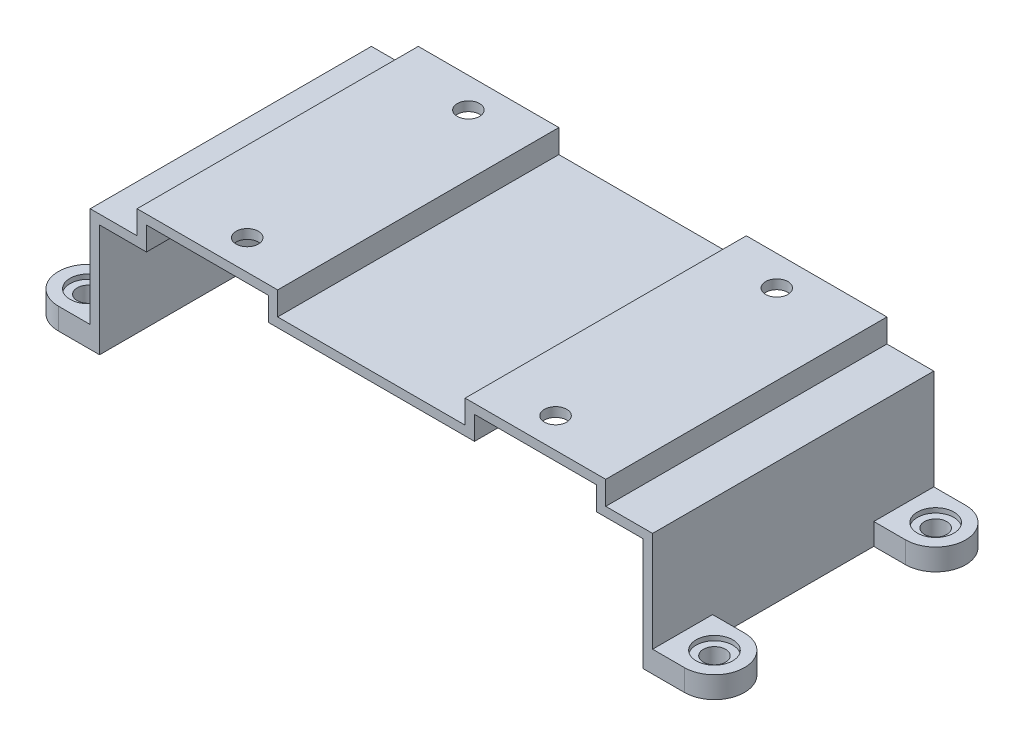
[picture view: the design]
ISO-10303-21;
HEADER;
FILE_DESCRIPTION(('STEP AP214'),'2;1');
FILE_NAME('part.step','',(''),(''),'','','');
FILE_SCHEMA(('AUTOMOTIVE_DESIGN { 1 0 10303 214 1 1 1 1 }'));
ENDSEC;
DATA;
#1=APPLICATION_CONTEXT('core data for automotive mechanical design processes');
#2=APPLICATION_PROTOCOL_DEFINITION('international standard','automotive_design',2000,#1);
#3=PRODUCT_CONTEXT('',#1,'mechanical');
#4=PRODUCT('Part','Part','',(#3));
#5=PRODUCT_RELATED_PRODUCT_CATEGORY('part','',(#4));
#6=PRODUCT_DEFINITION_FORMATION('','',#4);
#7=PRODUCT_DEFINITION_CONTEXT('part definition',#1,'design');
#8=PRODUCT_DEFINITION('design','',#6,#7);
#9=PRODUCT_DEFINITION_SHAPE('','',#8);
#10=(LENGTH_UNIT() NAMED_UNIT(*) SI_UNIT(.MILLI.,.METRE.));
#11=(NAMED_UNIT(*) PLANE_ANGLE_UNIT() SI_UNIT($,.RADIAN.));
#12=(NAMED_UNIT(*) SI_UNIT($,.STERADIAN.) SOLID_ANGLE_UNIT());
#13=UNCERTAINTY_MEASURE_WITH_UNIT(LENGTH_MEASURE(1.E-05),#10,'distance_accuracy_value','');
#14=(GEOMETRIC_REPRESENTATION_CONTEXT(3) GLOBAL_UNCERTAINTY_ASSIGNED_CONTEXT((#13)) GLOBAL_UNIT_ASSIGNED_CONTEXT((#10,
#11,#12)) REPRESENTATION_CONTEXT('',''));
#15=CARTESIAN_POINT('',(0.,0.,0.));
#16=DIRECTION('',(0.,0.,1.));
#17=DIRECTION('',(1.,0.,0.));
#18=AXIS2_PLACEMENT_3D('',#15,#16,#17);
#19=CARTESIAN_POINT('',(-84.836,5.84200000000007,8.12800000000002));
#20=DIRECTION('',(0.,1.,0.));
#21=DIRECTION('',(-1.,0.,0.));
#22=AXIS2_PLACEMENT_3D('',#19,#20,#21);
#23=PLANE('',#22);
#24=DIRECTION('',(0.,0.,-1.));
#25=VECTOR('',#24,1.);
#26=CARTESIAN_POINT('',(-76.2,5.84200000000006,0.));
#27=LINE('',#26,#25);
#28=CARTESIAN_POINT('',(-76.2,5.84200000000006,16.256));
#29=VERTEX_POINT('',#28);
#30=CARTESIAN_POINT('',(-76.2,5.84200000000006,0.));
#31=VERTEX_POINT('',#30);
#32=EDGE_CURVE('E316',#29,#31,#27,.T.);
#33=ORIENTED_EDGE('',*,*,#32,.T.);
#34=DIRECTION('',(-1.,0.,0.));
#35=VECTOR('',#34,1.);
#36=CARTESIAN_POINT('',(-76.2,5.84200000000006,0.));
#37=LINE('',#36,#35);
#38=CARTESIAN_POINT('',(-84.836,5.84200000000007,0.));
#39=VERTEX_POINT('',#38);
#40=EDGE_CURVE('E325',#31,#39,#37,.T.);
#41=ORIENTED_EDGE('',*,*,#40,.T.);
#42=CARTESIAN_POINT('',(-84.836,5.84200000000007,8.12800000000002));
#43=DIRECTION('',(0.,1.,0.));
#44=DIRECTION('',(-1.,0.,0.));
#45=AXIS2_PLACEMENT_3D('',#42,#43,#44);
#46=CIRCLE('',#45,8.128);
#47=CARTESIAN_POINT('',(-84.836,5.84200000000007,16.256));
#48=VERTEX_POINT('',#47);
#49=EDGE_CURVE('E323',#39,#48,#46,.T.);
#50=ORIENTED_EDGE('',*,*,#49,.T.);
#51=DIRECTION('',(1.,0.,0.));
#52=VECTOR('',#51,1.);
#53=CARTESIAN_POINT('',(-76.2,5.84200000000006,16.256));
#54=LINE('',#53,#52);
#55=EDGE_CURVE('E319',#48,#29,#54,.T.);
#56=ORIENTED_EDGE('',*,*,#55,.T.);
#57=EDGE_LOOP('',(#33,#41,#50,#56));
#58=FACE_BOUND('',#57,.T.);
#59=CARTESIAN_POINT('',(-84.836,5.84200000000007,8.12800000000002));
#60=DIRECTION('',(0.,-1.,0.));
#61=DIRECTION('',(-1.,0.,0.));
#62=AXIS2_PLACEMENT_3D('',#59,#60,#61);
#63=CIRCLE('',#62,4.95300000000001);
#64=CARTESIAN_POINT('',(-89.789,5.84200000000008,8.12800000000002));
#65=VERTEX_POINT('',#64);
#66=EDGE_CURVE('E313',#65,#65,#63,.T.);
#67=ORIENTED_EDGE('',*,*,#66,.T.);
#68=EDGE_LOOP('',(#67));
#69=FACE_BOUND('',#68,.T.);
#70=ADVANCED_FACE('F30',(#58,#69),#23,.T.);
#71=CARTESIAN_POINT('',(-76.2,33.02,76.2));
#72=DIRECTION('',(1.,0.,0.));
#73=DIRECTION('',(0.,1.,0.));
#74=AXIS2_PLACEMENT_3D('',#71,#72,#73);
#75=PLANE('',#74);
#76=DIRECTION('',(0.,-1.,0.));
#77=VECTOR('',#76,1.);
#78=CARTESIAN_POINT('',(-76.2,5.84200000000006,16.256));
#79=LINE('',#78,#77);
#80=CARTESIAN_POINT('',(-76.2,0.,16.256));
#81=VERTEX_POINT('',#80);
#82=EDGE_CURVE('E327',#29,#81,#79,.T.);
#83=ORIENTED_EDGE('',*,*,#82,.T.);
#84=DIRECTION('',(0.,0.,-1.));
#85=VECTOR('',#84,1.);
#86=CARTESIAN_POINT('',(-76.2,0.,76.2));
#87=LINE('',#86,#85);
#88=CARTESIAN_POINT('',(-76.2,0.,59.944));
#89=VERTEX_POINT('',#88);
#90=EDGE_CURVE('E707',#89,#81,#87,.T.);
#91=ORIENTED_EDGE('',*,*,#90,.F.);
#92=DIRECTION('',(0.,-1.,0.));
#93=VECTOR('',#92,1.);
#94=CARTESIAN_POINT('',(-76.2,5.84200000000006,59.944));
#95=LINE('',#94,#93);
#96=CARTESIAN_POINT('',(-76.2,5.84200000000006,59.944));
#97=VERTEX_POINT('',#96);
#98=EDGE_CURVE('E771',#97,#89,#95,.T.);
#99=ORIENTED_EDGE('',*,*,#98,.F.);
#100=DIRECTION('',(0.,0.,1.));
#101=VECTOR('',#100,1.);
#102=CARTESIAN_POINT('',(-76.2,5.84200000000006,76.2));
#103=LINE('',#102,#101);
#104=CARTESIAN_POINT('',(-76.2,5.84200000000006,76.2));
#105=VERTEX_POINT('',#104);
#106=EDGE_CURVE('E721',#97,#105,#103,.T.);
#107=ORIENTED_EDGE('',*,*,#106,.T.);
#108=DIRECTION('',(0.,-1.,0.));
#109=VECTOR('',#108,1.);
#110=CARTESIAN_POINT('',(-76.2,33.02,76.2));
#111=LINE('',#110,#109);
#112=CARTESIAN_POINT('',(-76.2,33.02,76.2));
#113=VERTEX_POINT('',#112);
#114=EDGE_CURVE('E715',#113,#105,#111,.T.);
#115=ORIENTED_EDGE('',*,*,#114,.F.);
#116=DIRECTION('',(0.,0.,-1.));
#117=VECTOR('',#116,1.);
#118=CARTESIAN_POINT('',(-76.2,33.02,76.2));
#119=LINE('',#118,#117);
#120=CARTESIAN_POINT('',(-76.2,33.02,0.));
#121=VERTEX_POINT('',#120);
#122=EDGE_CURVE('E710',#113,#121,#119,.T.);
#123=ORIENTED_EDGE('',*,*,#122,.T.);
#124=DIRECTION('',(0.,-1.,0.));
#125=VECTOR('',#124,1.);
#126=CARTESIAN_POINT('',(-76.2,33.02,0.));
#127=LINE('',#126,#125);
#128=EDGE_CURVE('E630',#121,#31,#127,.T.);
#129=ORIENTED_EDGE('',*,*,#128,.T.);
#130=ORIENTED_EDGE('',*,*,#32,.F.);
#131=EDGE_LOOP('',(#83,#91,#99,#107,#115,#123,#129,#130));
#132=FACE_BOUND('',#131,.T.);
#133=ADVANCED_FACE('F439',(#132),#75,.F.);
#134=CARTESIAN_POINT('',(84.836,5.84200000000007,68.072));
#135=DIRECTION('',(0.,1.,0.));
#136=DIRECTION('',(1.,0.,0.));
#137=AXIS2_PLACEMENT_3D('',#134,#135,#136);
#138=PLANE('',#137);
#139=DIRECTION('',(0.,0.,1.));
#140=VECTOR('',#139,1.);
#141=CARTESIAN_POINT('',(76.2,5.84200000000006,76.2));
#142=LINE('',#141,#140);
#143=CARTESIAN_POINT('',(76.2,5.84200000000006,59.944));
#144=VERTEX_POINT('',#143);
#145=CARTESIAN_POINT('',(76.2,5.84200000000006,76.2));
#146=VERTEX_POINT('',#145);
#147=EDGE_CURVE('E352',#144,#146,#142,.T.);
#148=ORIENTED_EDGE('',*,*,#147,.T.);
#149=DIRECTION('',(1.,0.,0.));
#150=VECTOR('',#149,1.);
#151=CARTESIAN_POINT('',(76.2,5.84200000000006,76.2));
#152=LINE('',#151,#150);
#153=CARTESIAN_POINT('',(84.836,5.84200000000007,76.2));
#154=VERTEX_POINT('',#153);
#155=EDGE_CURVE('E354',#146,#154,#152,.T.);
#156=ORIENTED_EDGE('',*,*,#155,.T.);
#157=CARTESIAN_POINT('',(84.836,5.84200000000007,68.072));
#158=DIRECTION('',(0.,1.,0.));
#159=DIRECTION('',(1.,0.,0.));
#160=AXIS2_PLACEMENT_3D('',#157,#158,#159);
#161=CIRCLE('',#160,8.128);
#162=CARTESIAN_POINT('',(84.836,5.84200000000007,59.944));
#163=VERTEX_POINT('',#162);
#164=EDGE_CURVE('E351',#154,#163,#161,.T.);
#165=ORIENTED_EDGE('',*,*,#164,.T.);
#166=DIRECTION('',(-1.,0.,0.));
#167=VECTOR('',#166,1.);
#168=CARTESIAN_POINT('',(76.2,5.84200000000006,59.944));
#169=LINE('',#168,#167);
#170=EDGE_CURVE('E349',#163,#144,#169,.T.);
#171=ORIENTED_EDGE('',*,*,#170,.T.);
#172=EDGE_LOOP('',(#148,#156,#165,#171));
#173=FACE_BOUND('',#172,.T.);
#174=CARTESIAN_POINT('',(84.836,5.84200000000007,68.072));
#175=DIRECTION('',(0.,-1.,0.));
#176=DIRECTION('',(1.,0.,0.));
#177=AXIS2_PLACEMENT_3D('',#174,#175,#176);
#178=CIRCLE('',#177,4.95300000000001);
#179=CARTESIAN_POINT('',(89.789,5.84200000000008,68.072));
#180=VERTEX_POINT('',#179);
#181=EDGE_CURVE('E346',#180,#180,#178,.T.);
#182=ORIENTED_EDGE('',*,*,#181,.T.);
#183=EDGE_LOOP('',(#182));
#184=FACE_BOUND('',#183,.T.);
#185=ADVANCED_FACE('F445',(#173,#184),#138,.T.);
#186=CARTESIAN_POINT('',(76.2,33.02,76.2));
#187=DIRECTION('',(-1.,0.,0.));
#188=DIRECTION('',(0.,-1.,0.));
#189=AXIS2_PLACEMENT_3D('',#186,#187,#188);
#190=PLANE('',#189);
#191=DIRECTION('',(0.,0.,-1.));
#192=VECTOR('',#191,1.);
#193=CARTESIAN_POINT('',(76.2,0.,76.2));
#194=LINE('',#193,#192);
#195=CARTESIAN_POINT('',(76.2,0.,59.944));
#196=VERTEX_POINT('',#195);
#197=CARTESIAN_POINT('',(76.2,0.,16.256));
#198=VERTEX_POINT('',#197);
#199=EDGE_CURVE('E52',#196,#198,#194,.T.);
#200=ORIENTED_EDGE('',*,*,#199,.T.);
#201=DIRECTION('',(0.,-1.,0.));
#202=VECTOR('',#201,1.);
#203=CARTESIAN_POINT('',(76.2,5.84200000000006,16.256));
#204=LINE('',#203,#202);
#205=CARTESIAN_POINT('',(76.2,5.84200000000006,16.256));
#206=VERTEX_POINT('',#205);
#207=EDGE_CURVE('E47',#206,#198,#204,.T.);
#208=ORIENTED_EDGE('',*,*,#207,.F.);
#209=DIRECTION('',(0.,0.,-1.));
#210=VECTOR('',#209,1.);
#211=CARTESIAN_POINT('',(76.2,5.84200000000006,0.));
#212=LINE('',#211,#210);
#213=CARTESIAN_POINT('',(76.2,5.84200000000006,0.));
#214=VERTEX_POINT('',#213);
#215=EDGE_CURVE('E277',#206,#214,#212,.T.);
#216=ORIENTED_EDGE('',*,*,#215,.T.);
#217=DIRECTION('',(0.,1.,0.));
#218=VECTOR('',#217,1.);
#219=CARTESIAN_POINT('',(76.2,33.02,0.));
#220=LINE('',#219,#218);
#221=CARTESIAN_POINT('',(76.2,33.02,0.));
#222=VERTEX_POINT('',#221);
#223=EDGE_CURVE('E265',#214,#222,#220,.T.);
#224=ORIENTED_EDGE('',*,*,#223,.T.);
#225=DIRECTION('',(0.,0.,-1.));
#226=VECTOR('',#225,1.);
#227=CARTESIAN_POINT('',(76.2,33.02,76.2));
#228=LINE('',#227,#226);
#229=CARTESIAN_POINT('',(76.2,33.02,76.2));
#230=VERTEX_POINT('',#229);
#231=EDGE_CURVE('E668',#230,#222,#228,.T.);
#232=ORIENTED_EDGE('',*,*,#231,.F.);
#233=DIRECTION('',(0.,1.,0.));
#234=VECTOR('',#233,1.);
#235=CARTESIAN_POINT('',(76.2,33.02,76.2));
#236=LINE('',#235,#234);
#237=EDGE_CURVE('E753',#146,#230,#236,.T.);
#238=ORIENTED_EDGE('',*,*,#237,.F.);
#239=ORIENTED_EDGE('',*,*,#147,.F.);
#240=DIRECTION('',(0.,-1.,0.));
#241=VECTOR('',#240,1.);
#242=CARTESIAN_POINT('',(76.2,5.84200000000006,59.944));
#243=LINE('',#242,#241);
#244=EDGE_CURVE('E364',#144,#196,#243,.T.);
#245=ORIENTED_EDGE('',*,*,#244,.T.);
#246=EDGE_LOOP('',(#200,#208,#216,#224,#232,#238,#239,#245));
#247=FACE_BOUND('',#246,.T.);
#248=ADVANCED_FACE('F278',(#247),#190,.F.);
#249=CARTESIAN_POINT('',(25.4,39.37,76.2));
#250=DIRECTION('',(0.,-1.,0.));
#251=DIRECTION('',(0.,0.,-1.));
#252=AXIS2_PLACEMENT_3D('',#249,#250,#251);
#253=PLANE('',#252);
#254=CARTESIAN_POINT('',(41.783,39.37,68.072));
#255=DIRECTION('',(0.,1.,0.));
#256=DIRECTION('',(-1.,0.,0.));
#257=AXIS2_PLACEMENT_3D('',#254,#255,#256);
#258=CIRCLE('',#257,3.02259999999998);
#259=CARTESIAN_POINT('',(38.7604,39.37,68.072));
#260=VERTEX_POINT('',#259);
#261=EDGE_CURVE('E411',#260,#260,#258,.T.);
#262=ORIENTED_EDGE('',*,*,#261,.F.);
#263=EDGE_LOOP('',(#262));
#264=FACE_BOUND('',#263,.T.);
#265=CARTESIAN_POINT('',(41.783,39.37,8.12800000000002));
#266=DIRECTION('',(0.,1.,0.));
#267=DIRECTION('',(-1.,0.,0.));
#268=AXIS2_PLACEMENT_3D('',#265,#266,#267);
#269=CIRCLE('',#268,3.02259999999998);
#270=CARTESIAN_POINT('',(38.7604,39.37,8.12800000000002));
#271=VERTEX_POINT('',#270);
#272=EDGE_CURVE('E401',#271,#271,#269,.T.);
#273=ORIENTED_EDGE('',*,*,#272,.F.);
#274=EDGE_LOOP('',(#273));
#275=FACE_BOUND('',#274,.T.);
#276=DIRECTION('',(-1.,0.,0.));
#277=VECTOR('',#276,1.);
#278=CARTESIAN_POINT('',(25.4,39.37,0.));
#279=LINE('',#278,#277);
#280=CARTESIAN_POINT('',(63.5,39.37,0.));
#281=VERTEX_POINT('',#280);
#282=CARTESIAN_POINT('',(25.4,39.37,0.));
#283=VERTEX_POINT('',#282);
#284=EDGE_CURVE('E610',#281,#283,#279,.T.);
#285=ORIENTED_EDGE('',*,*,#284,.T.);
#286=DIRECTION('',(0.,0.,-1.));
#287=VECTOR('',#286,1.);
#288=CARTESIAN_POINT('',(25.4,39.37,76.2));
#289=LINE('',#288,#287);
#290=CARTESIAN_POINT('',(25.4,39.37,76.2));
#291=VERTEX_POINT('',#290);
#292=EDGE_CURVE('E11',#291,#283,#289,.T.);
#293=ORIENTED_EDGE('',*,*,#292,.F.);
#294=DIRECTION('',(-1.,0.,0.));
#295=VECTOR('',#294,1.);
#296=CARTESIAN_POINT('',(25.4,39.37,76.2));
#297=LINE('',#296,#295);
#298=CARTESIAN_POINT('',(63.5,39.37,76.2));
#299=VERTEX_POINT('',#298);
#300=EDGE_CURVE('E660',#299,#291,#297,.T.);
#301=ORIENTED_EDGE('',*,*,#300,.F.);
#302=DIRECTION('',(0.,0.,-1.));
#303=VECTOR('',#302,1.);
#304=CARTESIAN_POINT('',(63.5,39.37,76.2));
#305=LINE('',#304,#303);
#306=EDGE_CURVE('E661',#299,#281,#305,.T.);
#307=ORIENTED_EDGE('',*,*,#306,.T.);
#308=EDGE_LOOP('',(#285,#293,#301,#307));
#309=FACE_BOUND('',#308,.T.);
#310=ADVANCED_FACE('F32',(#264,#275,#309),#253,.F.);
#311=CARTESIAN_POINT('',(25.4,33.02,76.2));
#312=DIRECTION('',(1.,0.,0.));
#313=DIRECTION('',(0.,0.,-1.));
#314=AXIS2_PLACEMENT_3D('',#311,#312,#313);
#315=PLANE('',#314);
#316=DIRECTION('',(0.,-1.,0.));
#317=VECTOR('',#316,1.);
#318=CARTESIAN_POINT('',(25.4,33.02,0.));
#319=LINE('',#318,#317);
#320=CARTESIAN_POINT('',(25.4,33.02,0.));
#321=VERTEX_POINT('',#320);
#322=EDGE_CURVE('E603',#283,#321,#319,.T.);
#323=ORIENTED_EDGE('',*,*,#322,.T.);
#324=DIRECTION('',(0.,0.,-1.));
#325=VECTOR('',#324,1.);
#326=CARTESIAN_POINT('',(25.4,33.02,76.2));
#327=LINE('',#326,#325);
#328=CARTESIAN_POINT('',(25.4,33.02,76.2));
#329=VERTEX_POINT('',#328);
#330=EDGE_CURVE('E39',#329,#321,#327,.T.);
#331=ORIENTED_EDGE('',*,*,#330,.F.);
#332=DIRECTION('',(0.,-1.,0.));
#333=VECTOR('',#332,1.);
#334=CARTESIAN_POINT('',(25.4,33.02,76.2));
#335=LINE('',#334,#333);
#336=EDGE_CURVE('E814',#291,#329,#335,.T.);
#337=ORIENTED_EDGE('',*,*,#336,.F.);
#338=ORIENTED_EDGE('',*,*,#292,.T.);
#339=EDGE_LOOP('',(#323,#331,#337,#338));
#340=FACE_BOUND('',#339,.T.);
#341=ADVANCED_FACE('F594',(#340),#315,.F.);
#342=CARTESIAN_POINT('',(-25.4,33.02,76.2));
#343=DIRECTION('',(0.,-1.,0.));
#344=DIRECTION('',(1.,0.,0.));
#345=AXIS2_PLACEMENT_3D('',#342,#343,#344);
#346=PLANE('',#345);
#347=DIRECTION('',(-1.,0.,0.));
#348=VECTOR('',#347,1.);
#349=CARTESIAN_POINT('',(-25.4,33.02,0.));
#350=LINE('',#349,#348);
#351=CARTESIAN_POINT('',(-25.4,33.02,0.));
#352=VERTEX_POINT('',#351);
#353=EDGE_CURVE('E609',#321,#352,#350,.T.);
#354=ORIENTED_EDGE('',*,*,#353,.T.);
#355=DIRECTION('',(0.,0.,-1.));
#356=VECTOR('',#355,1.);
#357=CARTESIAN_POINT('',(-25.4,33.02,76.2));
#358=LINE('',#357,#356);
#359=CARTESIAN_POINT('',(-25.4,33.02,76.2));
#360=VERTEX_POINT('',#359);
#361=EDGE_CURVE('E615',#360,#352,#358,.T.);
#362=ORIENTED_EDGE('',*,*,#361,.F.);
#363=DIRECTION('',(-1.,0.,0.));
#364=VECTOR('',#363,1.);
#365=CARTESIAN_POINT('',(-25.4,33.02,76.2));
#366=LINE('',#365,#364);
#367=EDGE_CURVE('E614',#329,#360,#366,.T.);
#368=ORIENTED_EDGE('',*,*,#367,.F.);
#369=ORIENTED_EDGE('',*,*,#330,.T.);
#370=EDGE_LOOP('',(#354,#362,#368,#369));
#371=FACE_BOUND('',#370,.T.);
#372=ADVANCED_FACE('F591',(#371),#346,.F.);
#373=CARTESIAN_POINT('',(-25.4,33.02,76.2));
#374=DIRECTION('',(-1.,0.,0.));
#375=DIRECTION('',(0.,0.,1.));
#376=AXIS2_PLACEMENT_3D('',#373,#374,#375);
#377=PLANE('',#376);
#378=DIRECTION('',(0.,1.,0.));
#379=VECTOR('',#378,1.);
#380=CARTESIAN_POINT('',(-25.4,33.02,0.));
#381=LINE('',#380,#379);
#382=CARTESIAN_POINT('',(-25.4,39.37,0.));
#383=VERTEX_POINT('',#382);
#384=EDGE_CURVE('E619',#352,#383,#381,.T.);
#385=ORIENTED_EDGE('',*,*,#384,.T.);
#386=DIRECTION('',(0.,0.,-1.));
#387=VECTOR('',#386,1.);
#388=CARTESIAN_POINT('',(-25.4,39.37,76.2));
#389=LINE('',#388,#387);
#390=CARTESIAN_POINT('',(-25.4,39.37,76.2));
#391=VERTEX_POINT('',#390);
#392=EDGE_CURVE('E802',#391,#383,#389,.T.);
#393=ORIENTED_EDGE('',*,*,#392,.F.);
#394=DIRECTION('',(0.,1.,0.));
#395=VECTOR('',#394,1.);
#396=CARTESIAN_POINT('',(-25.4,33.02,76.2));
#397=LINE('',#396,#395);
#398=EDGE_CURVE('E809',#360,#391,#397,.T.);
#399=ORIENTED_EDGE('',*,*,#398,.F.);
#400=ORIENTED_EDGE('',*,*,#361,.T.);
#401=EDGE_LOOP('',(#385,#393,#399,#400));
#402=FACE_BOUND('',#401,.T.);
#403=ADVANCED_FACE('F587',(#402),#377,.F.);
#404=CARTESIAN_POINT('',(-63.5,39.37,76.2));
#405=DIRECTION('',(0.,-1.,0.));
#406=DIRECTION('',(1.,0.,0.));
#407=AXIS2_PLACEMENT_3D('',#404,#405,#406);
#408=PLANE('',#407);
#409=CARTESIAN_POINT('',(-41.783,39.37,68.072));
#410=DIRECTION('',(0.,1.,0.));
#411=DIRECTION('',(-1.,0.,0.));
#412=AXIS2_PLACEMENT_3D('',#409,#410,#411);
#413=CIRCLE('',#412,3.02259999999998);
#414=CARTESIAN_POINT('',(-44.8056,39.37,68.072));
#415=VERTEX_POINT('',#414);
#416=EDGE_CURVE('E398',#415,#415,#413,.T.);
#417=ORIENTED_EDGE('',*,*,#416,.F.);
#418=EDGE_LOOP('',(#417));
#419=FACE_BOUND('',#418,.T.);
#420=CARTESIAN_POINT('',(-41.783,39.37,8.12800000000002));
#421=DIRECTION('',(0.,1.,0.));
#422=DIRECTION('',(-1.,0.,0.));
#423=AXIS2_PLACEMENT_3D('',#420,#421,#422);
#424=CIRCLE('',#423,3.02259999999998);
#425=CARTESIAN_POINT('',(-44.8056,39.37,8.12800000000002));
#426=VERTEX_POINT('',#425);
#427=EDGE_CURVE('E395',#426,#426,#424,.T.);
#428=ORIENTED_EDGE('',*,*,#427,.F.);
#429=EDGE_LOOP('',(#428));
#430=FACE_BOUND('',#429,.T.);
#431=DIRECTION('',(-1.,0.,0.));
#432=VECTOR('',#431,1.);
#433=CARTESIAN_POINT('',(-63.5,39.37,0.));
#434=LINE('',#433,#432);
#435=CARTESIAN_POINT('',(-63.5,39.37,0.));
#436=VERTEX_POINT('',#435);
#437=EDGE_CURVE('E621',#383,#436,#434,.T.);
#438=ORIENTED_EDGE('',*,*,#437,.T.);
#439=DIRECTION('',(0.,0.,-1.));
#440=VECTOR('',#439,1.);
#441=CARTESIAN_POINT('',(-63.5,39.37,76.2));
#442=LINE('',#441,#440);
#443=CARTESIAN_POINT('',(-63.5,39.37,76.2));
#444=VERTEX_POINT('',#443);
#445=EDGE_CURVE('E800',#444,#436,#442,.T.);
#446=ORIENTED_EDGE('',*,*,#445,.F.);
#447=DIRECTION('',(-1.,0.,0.));
#448=VECTOR('',#447,1.);
#449=CARTESIAN_POINT('',(-63.5,39.37,76.2));
#450=LINE('',#449,#448);
#451=EDGE_CURVE('E811',#391,#444,#450,.T.);
#452=ORIENTED_EDGE('',*,*,#451,.F.);
#453=ORIENTED_EDGE('',*,*,#392,.T.);
#454=EDGE_LOOP('',(#438,#446,#452,#453));
#455=FACE_BOUND('',#454,.T.);
#456=ADVANCED_FACE('F583',(#419,#430,#455),#408,.F.);
#457=CARTESIAN_POINT('',(-63.5,39.37,76.2));
#458=DIRECTION('',(1.,0.,0.));
#459=DIRECTION('',(0.,0.,-1.));
#460=AXIS2_PLACEMENT_3D('',#457,#458,#459);
#461=PLANE('',#460);
#462=DIRECTION('',(0.,-1.,0.));
#463=VECTOR('',#462,1.);
#464=CARTESIAN_POINT('',(-63.5,39.37,0.));
#465=LINE('',#464,#463);
#466=CARTESIAN_POINT('',(-63.5,33.02,0.));
#467=VERTEX_POINT('',#466);
#468=EDGE_CURVE('E626',#436,#467,#465,.T.);
#469=ORIENTED_EDGE('',*,*,#468,.T.);
#470=DIRECTION('',(0.,0.,-1.));
#471=VECTOR('',#470,1.);
#472=CARTESIAN_POINT('',(-63.5,33.02,76.2));
#473=LINE('',#472,#471);
#474=CARTESIAN_POINT('',(-63.5,33.02,76.2));
#475=VERTEX_POINT('',#474);
#476=EDGE_CURVE('E799',#475,#467,#473,.T.);
#477=ORIENTED_EDGE('',*,*,#476,.F.);
#478=DIRECTION('',(0.,-1.,0.));
#479=VECTOR('',#478,1.);
#480=CARTESIAN_POINT('',(-63.5,39.37,76.2));
#481=LINE('',#480,#479);
#482=EDGE_CURVE('E794',#444,#475,#481,.T.);
#483=ORIENTED_EDGE('',*,*,#482,.F.);
#484=ORIENTED_EDGE('',*,*,#445,.T.);
#485=EDGE_LOOP('',(#469,#477,#483,#484));
#486=FACE_BOUND('',#485,.T.);
#487=ADVANCED_FACE('F579',(#486),#461,.F.);
#488=CARTESIAN_POINT('',(-76.2,33.02,76.2));
#489=DIRECTION('',(0.,-1.,0.));
#490=DIRECTION('',(0.,0.,-1.));
#491=AXIS2_PLACEMENT_3D('',#488,#489,#490);
#492=PLANE('',#491);
#493=DIRECTION('',(-1.,0.,0.));
#494=VECTOR('',#493,1.);
#495=CARTESIAN_POINT('',(-76.2,33.02,0.));
#496=LINE('',#495,#494);
#497=EDGE_CURVE('E628',#467,#121,#496,.T.);
#498=ORIENTED_EDGE('',*,*,#497,.T.);
#499=ORIENTED_EDGE('',*,*,#122,.F.);
#500=DIRECTION('',(-1.,0.,0.));
#501=VECTOR('',#500,1.);
#502=CARTESIAN_POINT('',(-76.2,33.02,76.2));
#503=LINE('',#502,#501);
#504=EDGE_CURVE('E720',#475,#113,#503,.T.);
#505=ORIENTED_EDGE('',*,*,#504,.F.);
#506=ORIENTED_EDGE('',*,*,#476,.T.);
#507=EDGE_LOOP('',(#498,#499,#505,#506));
#508=FACE_BOUND('',#507,.T.);
#509=ADVANCED_FACE('F574',(#508),#492,.F.);
#510=CARTESIAN_POINT('',(-76.2,0.,76.2));
#511=DIRECTION('',(0.,1.,0.));
#512=DIRECTION('',(-1.,0.,0.));
#513=AXIS2_PLACEMENT_3D('',#510,#511,#512);
#514=PLANE('',#513);
#515=CARTESIAN_POINT('',(-84.836,0.,8.12800000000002));
#516=DIRECTION('',(0.,1.,0.));
#517=DIRECTION('',(-1.,0.,0.));
#518=AXIS2_PLACEMENT_3D('',#515,#516,#517);
#519=CIRCLE('',#518,3.02259999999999);
#520=CARTESIAN_POINT('',(-87.8586,0.,8.12800000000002));
#521=VERTEX_POINT('',#520);
#522=EDGE_CURVE('E308',#521,#521,#519,.T.);
#523=ORIENTED_EDGE('',*,*,#522,.T.);
#524=EDGE_LOOP('',(#523));
#525=FACE_BOUND('',#524,.T.);
#526=CARTESIAN_POINT('',(-84.836,0.,68.072));
#527=DIRECTION('',(0.,1.,0.));
#528=DIRECTION('',(-1.,0.,0.));
#529=AXIS2_PLACEMENT_3D('',#526,#527,#528);
#530=CIRCLE('',#529,3.02259999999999);
#531=CARTESIAN_POINT('',(-87.8586,0.,68.072));
#532=VERTEX_POINT('',#531);
#533=EDGE_CURVE('E759',#532,#532,#530,.T.);
#534=ORIENTED_EDGE('',*,*,#533,.T.);
#535=EDGE_LOOP('',(#534));
#536=FACE_BOUND('',#535,.T.);
#537=DIRECTION('',(1.,0.,0.));
#538=VECTOR('',#537,1.);
#539=CARTESIAN_POINT('',(-76.2,0.,0.));
#540=LINE('',#539,#538);
#541=CARTESIAN_POINT('',(-84.836,0.,0.));
#542=VERTEX_POINT('',#541);
#543=CARTESIAN_POINT('',(-73.66,0.,0.));
#544=VERTEX_POINT('',#543);
#545=EDGE_CURVE('E632',#542,#544,#540,.T.);
#546=ORIENTED_EDGE('',*,*,#545,.T.);
#547=DIRECTION('',(0.,0.,-1.));
#548=VECTOR('',#547,1.);
#549=CARTESIAN_POINT('',(-73.66,0.,76.2));
#550=LINE('',#549,#548);
#551=CARTESIAN_POINT('',(-73.66,0.,76.2));
#552=VERTEX_POINT('',#551);
#553=EDGE_CURVE('E704',#552,#544,#550,.T.);
#554=ORIENTED_EDGE('',*,*,#553,.F.);
#555=DIRECTION('',(1.,0.,0.));
#556=VECTOR('',#555,1.);
#557=CARTESIAN_POINT('',(-76.2,0.,76.2));
#558=LINE('',#557,#556);
#559=CARTESIAN_POINT('',(-84.836,0.,76.2));
#560=VERTEX_POINT('',#559);
#561=EDGE_CURVE('E719',#560,#552,#558,.T.);
#562=ORIENTED_EDGE('',*,*,#561,.F.);
#563=CARTESIAN_POINT('',(-84.836,0.,68.072));
#564=DIRECTION('',(0.,-1.,0.));
#565=DIRECTION('',(-1.,0.,0.));
#566=AXIS2_PLACEMENT_3D('',#563,#564,#565);
#567=CIRCLE('',#566,8.128);
#568=CARTESIAN_POINT('',(-84.836,0.,59.944));
#569=VERTEX_POINT('',#568);
#570=EDGE_CURVE('E768',#560,#569,#567,.T.);
#571=ORIENTED_EDGE('',*,*,#570,.T.);
#572=DIRECTION('',(1.,0.,0.));
#573=VECTOR('',#572,1.);
#574=CARTESIAN_POINT('',(-76.2,0.,59.944));
#575=LINE('',#574,#573);
#576=EDGE_CURVE('E765',#569,#89,#575,.T.);
#577=ORIENTED_EDGE('',*,*,#576,.T.);
#578=ORIENTED_EDGE('',*,*,#90,.T.);
#579=DIRECTION('',(1.,0.,0.));
#580=VECTOR('',#579,1.);
#581=CARTESIAN_POINT('',(-76.2,0.,16.256));
#582=LINE('',#581,#580);
#583=CARTESIAN_POINT('',(-84.836,0.,16.256));
#584=VERTEX_POINT('',#583);
#585=EDGE_CURVE('E312',#584,#81,#582,.T.);
#586=ORIENTED_EDGE('',*,*,#585,.F.);
#587=CARTESIAN_POINT('',(-84.836,0.,8.12800000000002));
#588=DIRECTION('',(0.,1.,0.));
#589=DIRECTION('',(-1.,0.,0.));
#590=AXIS2_PLACEMENT_3D('',#587,#588,#589);
#591=CIRCLE('',#590,8.128);
#592=EDGE_CURVE('E320',#542,#584,#591,.T.);
#593=ORIENTED_EDGE('',*,*,#592,.F.);
#594=EDGE_LOOP('',(#546,#554,#562,#571,#577,#578,#586,#593));
#595=FACE_BOUND('',#594,.T.);
#596=ADVANCED_FACE('F571',(#525,#536,#595),#514,.F.);
#597=CARTESIAN_POINT('',(-73.66,30.48,76.2));
#598=DIRECTION('',(-1.,0.,0.));
#599=DIRECTION('',(0.,0.,1.));
#600=AXIS2_PLACEMENT_3D('',#597,#598,#599);
#601=PLANE('',#600);
#602=DIRECTION('',(0.,1.,0.));
#603=VECTOR('',#602,1.);
#604=CARTESIAN_POINT('',(-73.66,30.48,0.));
#605=LINE('',#604,#603);
#606=CARTESIAN_POINT('',(-73.66,30.48,0.));
#607=VERTEX_POINT('',#606);
#608=EDGE_CURVE('E634',#544,#607,#605,.T.);
#609=ORIENTED_EDGE('',*,*,#608,.T.);
#610=DIRECTION('',(0.,0.,-1.));
#611=VECTOR('',#610,1.);
#612=CARTESIAN_POINT('',(-73.66,30.48,76.2));
#613=LINE('',#612,#611);
#614=CARTESIAN_POINT('',(-73.66,30.48,76.2));
#615=VERTEX_POINT('',#614);
#616=EDGE_CURVE('E701',#615,#607,#613,.T.);
#617=ORIENTED_EDGE('',*,*,#616,.F.);
#618=DIRECTION('',(0.,1.,0.));
#619=VECTOR('',#618,1.);
#620=CARTESIAN_POINT('',(-73.66,30.48,76.2));
#621=LINE('',#620,#619);
#622=EDGE_CURVE('E729',#552,#615,#621,.T.);
#623=ORIENTED_EDGE('',*,*,#622,.F.);
#624=ORIENTED_EDGE('',*,*,#553,.T.);
#625=EDGE_LOOP('',(#609,#617,#623,#624));
#626=FACE_BOUND('',#625,.T.);
#627=ADVANCED_FACE('F567',(#626),#601,.F.);
#628=CARTESIAN_POINT('',(-73.66,30.48,76.2));
#629=DIRECTION('',(0.,1.,0.));
#630=DIRECTION('',(0.,0.,1.));
#631=AXIS2_PLACEMENT_3D('',#628,#629,#630);
#632=PLANE('',#631);
#633=DIRECTION('',(1.,0.,0.));
#634=VECTOR('',#633,1.);
#635=CARTESIAN_POINT('',(-73.66,30.48,0.));
#636=LINE('',#635,#634);
#637=CARTESIAN_POINT('',(-60.96,30.48,0.));
#638=VERTEX_POINT('',#637);
#639=EDGE_CURVE('E636',#607,#638,#636,.T.);
#640=ORIENTED_EDGE('',*,*,#639,.T.);
#641=DIRECTION('',(0.,0.,-1.));
#642=VECTOR('',#641,1.);
#643=CARTESIAN_POINT('',(-60.96,30.48,76.2));
#644=LINE('',#643,#642);
#645=CARTESIAN_POINT('',(-60.96,30.48,76.2));
#646=VERTEX_POINT('',#645);
#647=EDGE_CURVE('E698',#646,#638,#644,.T.);
#648=ORIENTED_EDGE('',*,*,#647,.F.);
#649=DIRECTION('',(1.,0.,0.));
#650=VECTOR('',#649,1.);
#651=CARTESIAN_POINT('',(-73.66,30.48,76.2));
#652=LINE('',#651,#650);
#653=EDGE_CURVE('E731',#615,#646,#652,.T.);
#654=ORIENTED_EDGE('',*,*,#653,.F.);
#655=ORIENTED_EDGE('',*,*,#616,.T.);
#656=EDGE_LOOP('',(#640,#648,#654,#655));
#657=FACE_BOUND('',#656,.T.);
#658=ADVANCED_FACE('F563',(#657),#632,.F.);
#659=CARTESIAN_POINT('',(-60.96,36.83,76.2));
#660=DIRECTION('',(-1.,0.,0.));
#661=DIRECTION('',(0.,0.,1.));
#662=AXIS2_PLACEMENT_3D('',#659,#660,#661);
#663=PLANE('',#662);
#664=DIRECTION('',(0.,1.,0.));
#665=VECTOR('',#664,1.);
#666=CARTESIAN_POINT('',(-60.96,36.83,0.));
#667=LINE('',#666,#665);
#668=CARTESIAN_POINT('',(-60.96,36.83,0.));
#669=VERTEX_POINT('',#668);
#670=EDGE_CURVE('E638',#638,#669,#667,.T.);
#671=ORIENTED_EDGE('',*,*,#670,.T.);
#672=DIRECTION('',(0.,0.,-1.));
#673=VECTOR('',#672,1.);
#674=CARTESIAN_POINT('',(-60.96,36.83,76.2));
#675=LINE('',#674,#673);
#676=CARTESIAN_POINT('',(-60.96,36.83,76.2));
#677=VERTEX_POINT('',#676);
#678=EDGE_CURVE('E695',#677,#669,#675,.T.);
#679=ORIENTED_EDGE('',*,*,#678,.F.);
#680=DIRECTION('',(0.,1.,0.));
#681=VECTOR('',#680,1.);
#682=CARTESIAN_POINT('',(-60.96,36.83,76.2));
#683=LINE('',#682,#681);
#684=EDGE_CURVE('E733',#646,#677,#683,.T.);
#685=ORIENTED_EDGE('',*,*,#684,.F.);
#686=ORIENTED_EDGE('',*,*,#647,.T.);
#687=EDGE_LOOP('',(#671,#679,#685,#686));
#688=FACE_BOUND('',#687,.T.);
#689=ADVANCED_FACE('F559',(#688),#663,.F.);
#690=CARTESIAN_POINT('',(-60.96,36.83,76.2));
#691=DIRECTION('',(0.,1.,0.));
#692=DIRECTION('',(-1.,0.,0.));
#693=AXIS2_PLACEMENT_3D('',#690,#691,#692);
#694=PLANE('',#693);
#695=CARTESIAN_POINT('',(-41.783,36.83,68.072));
#696=DIRECTION('',(0.,1.,0.));
#697=DIRECTION('',(-1.,0.,0.));
#698=AXIS2_PLACEMENT_3D('',#695,#696,#697);
#699=CIRCLE('',#698,3.02259999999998);
#700=CARTESIAN_POINT('',(-44.8056,36.83,68.072));
#701=VERTEX_POINT('',#700);
#702=EDGE_CURVE('E396',#701,#701,#699,.T.);
#703=ORIENTED_EDGE('',*,*,#702,.T.);
#704=EDGE_LOOP('',(#703));
#705=FACE_BOUND('',#704,.T.);
#706=CARTESIAN_POINT('',(-41.783,36.83,8.12800000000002));
#707=DIRECTION('',(0.,1.,0.));
#708=DIRECTION('',(-1.,0.,0.));
#709=AXIS2_PLACEMENT_3D('',#706,#707,#708);
#710=CIRCLE('',#709,3.02259999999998);
#711=CARTESIAN_POINT('',(-44.8056,36.83,8.12800000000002));
#712=VERTEX_POINT('',#711);
#713=EDGE_CURVE('E392',#712,#712,#710,.T.);
#714=ORIENTED_EDGE('',*,*,#713,.T.);
#715=EDGE_LOOP('',(#714));
#716=FACE_BOUND('',#715,.T.);
#717=DIRECTION('',(1.,0.,0.));
#718=VECTOR('',#717,1.);
#719=CARTESIAN_POINT('',(-60.96,36.83,0.));
#720=LINE('',#719,#718);
#721=CARTESIAN_POINT('',(-27.94,36.83,0.));
#722=VERTEX_POINT('',#721);
#723=EDGE_CURVE('E640',#669,#722,#720,.T.);
#724=ORIENTED_EDGE('',*,*,#723,.T.);
#725=DIRECTION('',(0.,0.,-1.));
#726=VECTOR('',#725,1.);
#727=CARTESIAN_POINT('',(-27.94,36.83,76.2));
#728=LINE('',#727,#726);
#729=CARTESIAN_POINT('',(-27.94,36.83,76.2));
#730=VERTEX_POINT('',#729);
#731=EDGE_CURVE('E692',#730,#722,#728,.T.);
#732=ORIENTED_EDGE('',*,*,#731,.F.);
#733=DIRECTION('',(1.,0.,0.));
#734=VECTOR('',#733,1.);
#735=CARTESIAN_POINT('',(-60.96,36.83,76.2));
#736=LINE('',#735,#734);
#737=EDGE_CURVE('E735',#677,#730,#736,.T.);
#738=ORIENTED_EDGE('',*,*,#737,.F.);
#739=ORIENTED_EDGE('',*,*,#678,.T.);
#740=EDGE_LOOP('',(#724,#732,#738,#739));
#741=FACE_BOUND('',#740,.T.);
#742=ADVANCED_FACE('F555',(#705,#716,#741),#694,.F.);
#743=CARTESIAN_POINT('',(-27.94,30.48,76.2));
#744=DIRECTION('',(1.,0.,0.));
#745=DIRECTION('',(0.,0.,-1.));
#746=AXIS2_PLACEMENT_3D('',#743,#744,#745);
#747=PLANE('',#746);
#748=DIRECTION('',(0.,-1.,0.));
#749=VECTOR('',#748,1.);
#750=CARTESIAN_POINT('',(-27.94,30.48,0.));
#751=LINE('',#750,#749);
#752=CARTESIAN_POINT('',(-27.94,30.48,0.));
#753=VERTEX_POINT('',#752);
#754=EDGE_CURVE('E642',#722,#753,#751,.T.);
#755=ORIENTED_EDGE('',*,*,#754,.T.);
#756=DIRECTION('',(0.,0.,-1.));
#757=VECTOR('',#756,1.);
#758=CARTESIAN_POINT('',(-27.94,30.48,76.2));
#759=LINE('',#758,#757);
#760=CARTESIAN_POINT('',(-27.94,30.48,76.2));
#761=VERTEX_POINT('',#760);
#762=EDGE_CURVE('E689',#761,#753,#759,.T.);
#763=ORIENTED_EDGE('',*,*,#762,.F.);
#764=DIRECTION('',(0.,-1.,0.));
#765=VECTOR('',#764,1.);
#766=CARTESIAN_POINT('',(-27.94,30.48,76.2));
#767=LINE('',#766,#765);
#768=EDGE_CURVE('E737',#730,#761,#767,.T.);
#769=ORIENTED_EDGE('',*,*,#768,.F.);
#770=ORIENTED_EDGE('',*,*,#731,.T.);
#771=EDGE_LOOP('',(#755,#763,#769,#770));
#772=FACE_BOUND('',#771,.T.);
#773=ADVANCED_FACE('F551',(#772),#747,.F.);
#774=CARTESIAN_POINT('',(-27.94,30.48,76.2));
#775=DIRECTION('',(0.,1.,0.));
#776=DIRECTION('',(0.,0.,1.));
#777=AXIS2_PLACEMENT_3D('',#774,#775,#776);
#778=PLANE('',#777);
#779=DIRECTION('',(1.,0.,0.));
#780=VECTOR('',#779,1.);
#781=CARTESIAN_POINT('',(-27.94,30.48,0.));
#782=LINE('',#781,#780);
#783=CARTESIAN_POINT('',(27.94,30.48,0.));
#784=VERTEX_POINT('',#783);
#785=EDGE_CURVE('E644',#753,#784,#782,.T.);
#786=ORIENTED_EDGE('',*,*,#785,.T.);
#787=DIRECTION('',(0.,0.,-1.));
#788=VECTOR('',#787,1.);
#789=CARTESIAN_POINT('',(27.94,30.48,76.2));
#790=LINE('',#789,#788);
#791=CARTESIAN_POINT('',(27.94,30.48,76.2));
#792=VERTEX_POINT('',#791);
#793=EDGE_CURVE('E686',#792,#784,#790,.T.);
#794=ORIENTED_EDGE('',*,*,#793,.F.);
#795=DIRECTION('',(1.,0.,0.));
#796=VECTOR('',#795,1.);
#797=CARTESIAN_POINT('',(-27.94,30.48,76.2));
#798=LINE('',#797,#796);
#799=EDGE_CURVE('E739',#761,#792,#798,.T.);
#800=ORIENTED_EDGE('',*,*,#799,.F.);
#801=ORIENTED_EDGE('',*,*,#762,.T.);
#802=EDGE_LOOP('',(#786,#794,#800,#801));
#803=FACE_BOUND('',#802,.T.);
#804=ADVANCED_FACE('F547',(#803),#778,.F.);
#805=CARTESIAN_POINT('',(27.94,30.48,76.2));
#806=DIRECTION('',(-1.,0.,0.));
#807=DIRECTION('',(0.,0.,1.));
#808=AXIS2_PLACEMENT_3D('',#805,#806,#807);
#809=PLANE('',#808);
#810=DIRECTION('',(0.,1.,0.));
#811=VECTOR('',#810,1.);
#812=CARTESIAN_POINT('',(27.94,30.48,0.));
#813=LINE('',#812,#811);
#814=CARTESIAN_POINT('',(27.94,36.83,0.));
#815=VERTEX_POINT('',#814);
#816=EDGE_CURVE('E646',#784,#815,#813,.T.);
#817=ORIENTED_EDGE('',*,*,#816,.T.);
#818=DIRECTION('',(0.,0.,-1.));
#819=VECTOR('',#818,1.);
#820=CARTESIAN_POINT('',(27.94,36.83,76.2));
#821=LINE('',#820,#819);
#822=CARTESIAN_POINT('',(27.94,36.83,76.2));
#823=VERTEX_POINT('',#822);
#824=EDGE_CURVE('E683',#823,#815,#821,.T.);
#825=ORIENTED_EDGE('',*,*,#824,.F.);
#826=DIRECTION('',(0.,1.,0.));
#827=VECTOR('',#826,1.);
#828=CARTESIAN_POINT('',(27.94,30.48,76.2));
#829=LINE('',#828,#827);
#830=EDGE_CURVE('E741',#792,#823,#829,.T.);
#831=ORIENTED_EDGE('',*,*,#830,.F.);
#832=ORIENTED_EDGE('',*,*,#793,.T.);
#833=EDGE_LOOP('',(#817,#825,#831,#832));
#834=FACE_BOUND('',#833,.T.);
#835=ADVANCED_FACE('F543',(#834),#809,.F.);
#836=CARTESIAN_POINT('',(27.94,36.83,76.2));
#837=DIRECTION('',(0.,1.,0.));
#838=DIRECTION('',(-1.,0.,0.));
#839=AXIS2_PLACEMENT_3D('',#836,#837,#838);
#840=PLANE('',#839);
#841=CARTESIAN_POINT('',(41.783,36.83,68.072));
#842=DIRECTION('',(0.,1.,0.));
#843=DIRECTION('',(-1.,0.,0.));
#844=AXIS2_PLACEMENT_3D('',#841,#842,#843);
#845=CIRCLE('',#844,3.02259999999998);
#846=CARTESIAN_POINT('',(38.7604,36.83,68.072));
#847=VERTEX_POINT('',#846);
#848=EDGE_CURVE('E34',#847,#847,#845,.T.);
#849=ORIENTED_EDGE('',*,*,#848,.T.);
#850=EDGE_LOOP('',(#849));
#851=FACE_BOUND('',#850,.T.);
#852=CARTESIAN_POINT('',(41.783,36.83,8.12800000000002));
#853=DIRECTION('',(0.,1.,0.));
#854=DIRECTION('',(-1.,0.,0.));
#855=AXIS2_PLACEMENT_3D('',#852,#853,#854);
#856=CIRCLE('',#855,3.02259999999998);
#857=CARTESIAN_POINT('',(38.7604,36.83,8.12800000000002));
#858=VERTEX_POINT('',#857);
#859=EDGE_CURVE('E399',#858,#858,#856,.T.);
#860=ORIENTED_EDGE('',*,*,#859,.T.);
#861=EDGE_LOOP('',(#860));
#862=FACE_BOUND('',#861,.T.);
#863=DIRECTION('',(1.,0.,0.));
#864=VECTOR('',#863,1.);
#865=CARTESIAN_POINT('',(27.94,36.83,0.));
#866=LINE('',#865,#864);
#867=CARTESIAN_POINT('',(60.96,36.83,0.));
#868=VERTEX_POINT('',#867);
#869=EDGE_CURVE('E648',#815,#868,#866,.T.);
#870=ORIENTED_EDGE('',*,*,#869,.T.);
#871=DIRECTION('',(0.,0.,-1.));
#872=VECTOR('',#871,1.);
#873=CARTESIAN_POINT('',(60.96,36.83,76.2));
#874=LINE('',#873,#872);
#875=CARTESIAN_POINT('',(60.96,36.83,76.2));
#876=VERTEX_POINT('',#875);
#877=EDGE_CURVE('E680',#876,#868,#874,.T.);
#878=ORIENTED_EDGE('',*,*,#877,.F.);
#879=DIRECTION('',(1.,0.,0.));
#880=VECTOR('',#879,1.);
#881=CARTESIAN_POINT('',(27.94,36.83,76.2));
#882=LINE('',#881,#880);
#883=EDGE_CURVE('E743',#823,#876,#882,.T.);
#884=ORIENTED_EDGE('',*,*,#883,.F.);
#885=ORIENTED_EDGE('',*,*,#824,.T.);
#886=EDGE_LOOP('',(#870,#878,#884,#885));
#887=FACE_BOUND('',#886,.T.);
#888=ADVANCED_FACE('F539',(#851,#862,#887),#840,.F.);
#889=CARTESIAN_POINT('',(60.96,36.83,76.2));
#890=DIRECTION('',(1.,0.,0.));
#891=DIRECTION('',(0.,0.,-1.));
#892=AXIS2_PLACEMENT_3D('',#889,#890,#891);
#893=PLANE('',#892);
#894=DIRECTION('',(0.,-1.,0.));
#895=VECTOR('',#894,1.);
#896=CARTESIAN_POINT('',(60.96,36.83,0.));
#897=LINE('',#896,#895);
#898=CARTESIAN_POINT('',(60.96,30.48,0.));
#899=VERTEX_POINT('',#898);
#900=EDGE_CURVE('E650',#868,#899,#897,.T.);
#901=ORIENTED_EDGE('',*,*,#900,.T.);
#902=DIRECTION('',(0.,0.,-1.));
#903=VECTOR('',#902,1.);
#904=CARTESIAN_POINT('',(60.96,30.48,76.2));
#905=LINE('',#904,#903);
#906=CARTESIAN_POINT('',(60.96,30.48,76.2));
#907=VERTEX_POINT('',#906);
#908=EDGE_CURVE('E677',#907,#899,#905,.T.);
#909=ORIENTED_EDGE('',*,*,#908,.F.);
#910=DIRECTION('',(0.,-1.,0.));
#911=VECTOR('',#910,1.);
#912=CARTESIAN_POINT('',(60.96,36.83,76.2));
#913=LINE('',#912,#911);
#914=EDGE_CURVE('E745',#876,#907,#913,.T.);
#915=ORIENTED_EDGE('',*,*,#914,.F.);
#916=ORIENTED_EDGE('',*,*,#877,.T.);
#917=EDGE_LOOP('',(#901,#909,#915,#916));
#918=FACE_BOUND('',#917,.T.);
#919=ADVANCED_FACE('F535',(#918),#893,.F.);
#920=CARTESIAN_POINT('',(60.96,30.48,76.2));
#921=DIRECTION('',(0.,1.,0.));
#922=DIRECTION('',(0.,0.,1.));
#923=AXIS2_PLACEMENT_3D('',#920,#921,#922);
#924=PLANE('',#923);
#925=DIRECTION('',(1.,0.,0.));
#926=VECTOR('',#925,1.);
#927=CARTESIAN_POINT('',(60.96,30.48,0.));
#928=LINE('',#927,#926);
#929=CARTESIAN_POINT('',(73.66,30.48,0.));
#930=VERTEX_POINT('',#929);
#931=EDGE_CURVE('E652',#899,#930,#928,.T.);
#932=ORIENTED_EDGE('',*,*,#931,.T.);
#933=DIRECTION('',(0.,0.,-1.));
#934=VECTOR('',#933,1.);
#935=CARTESIAN_POINT('',(73.66,30.48,76.2));
#936=LINE('',#935,#934);
#937=CARTESIAN_POINT('',(73.66,30.48,76.2));
#938=VERTEX_POINT('',#937);
#939=EDGE_CURVE('E674',#938,#930,#936,.T.);
#940=ORIENTED_EDGE('',*,*,#939,.F.);
#941=DIRECTION('',(1.,0.,0.));
#942=VECTOR('',#941,1.);
#943=CARTESIAN_POINT('',(60.96,30.48,76.2));
#944=LINE('',#943,#942);
#945=EDGE_CURVE('E747',#907,#938,#944,.T.);
#946=ORIENTED_EDGE('',*,*,#945,.F.);
#947=ORIENTED_EDGE('',*,*,#908,.T.);
#948=EDGE_LOOP('',(#932,#940,#946,#947));
#949=FACE_BOUND('',#948,.T.);
#950=ADVANCED_FACE('F531',(#949),#924,.F.);
#951=CARTESIAN_POINT('',(73.66,30.48,76.2));
#952=DIRECTION('',(1.,0.,0.));
#953=DIRECTION('',(0.,0.,-1.));
#954=AXIS2_PLACEMENT_3D('',#951,#952,#953);
#955=PLANE('',#954);
#956=DIRECTION('',(0.,-1.,0.));
#957=VECTOR('',#956,1.);
#958=CARTESIAN_POINT('',(73.66,30.48,0.));
#959=LINE('',#958,#957);
#960=CARTESIAN_POINT('',(73.66,0.,0.));
#961=VERTEX_POINT('',#960);
#962=EDGE_CURVE('E654',#930,#961,#959,.T.);
#963=ORIENTED_EDGE('',*,*,#962,.T.);
#964=DIRECTION('',(0.,0.,-1.));
#965=VECTOR('',#964,1.);
#966=CARTESIAN_POINT('',(73.66,0.,76.2));
#967=LINE('',#966,#965);
#968=CARTESIAN_POINT('',(73.66,0.,76.2));
#969=VERTEX_POINT('',#968);
#970=EDGE_CURVE('E671',#969,#961,#967,.T.);
#971=ORIENTED_EDGE('',*,*,#970,.F.);
#972=DIRECTION('',(0.,-1.,0.));
#973=VECTOR('',#972,1.);
#974=CARTESIAN_POINT('',(73.66,30.48,76.2));
#975=LINE('',#974,#973);
#976=EDGE_CURVE('E749',#938,#969,#975,.T.);
#977=ORIENTED_EDGE('',*,*,#976,.F.);
#978=ORIENTED_EDGE('',*,*,#939,.T.);
#979=EDGE_LOOP('',(#963,#971,#977,#978));
#980=FACE_BOUND('',#979,.T.);
#981=ADVANCED_FACE('F527',(#980),#955,.F.);
#982=CARTESIAN_POINT('',(76.2,0.,76.2));
#983=DIRECTION('',(0.,1.,0.));
#984=DIRECTION('',(-1.,0.,0.));
#985=AXIS2_PLACEMENT_3D('',#982,#983,#984);
#986=PLANE('',#985);
#987=CARTESIAN_POINT('',(84.836,0.,8.12800000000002));
#988=DIRECTION('',(0.,1.,0.));
#989=DIRECTION('',(-1.,0.,0.));
#990=AXIS2_PLACEMENT_3D('',#987,#988,#989);
#991=CIRCLE('',#990,3.02259999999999);
#992=CARTESIAN_POINT('',(81.8134,0.,8.12800000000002));
#993=VERTEX_POINT('',#992);
#994=EDGE_CURVE('E387',#993,#993,#991,.T.);
#995=ORIENTED_EDGE('',*,*,#994,.T.);
#996=EDGE_LOOP('',(#995));
#997=FACE_BOUND('',#996,.T.);
#998=CARTESIAN_POINT('',(84.836,0.,68.072));
#999=DIRECTION('',(0.,1.,0.));
#1000=DIRECTION('',(-1.,0.,0.));
#1001=AXIS2_PLACEMENT_3D('',#998,#999,#1000);
#1002=CIRCLE('',#1001,3.02259999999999);
#1003=CARTESIAN_POINT('',(81.8134,0.,68.072));
#1004=VERTEX_POINT('',#1003);
#1005=EDGE_CURVE('E341',#1004,#1004,#1002,.T.);
#1006=ORIENTED_EDGE('',*,*,#1005,.T.);
#1007=EDGE_LOOP('',(#1006));
#1008=FACE_BOUND('',#1007,.T.);
#1009=DIRECTION('',(1.,0.,0.));
#1010=VECTOR('',#1009,1.);
#1011=CARTESIAN_POINT('',(76.2,0.,0.));
#1012=LINE('',#1011,#1010);
#1013=CARTESIAN_POINT('',(84.836,0.,0.));
#1014=VERTEX_POINT('',#1013);
#1015=EDGE_CURVE('E275',#961,#1014,#1012,.T.);
#1016=ORIENTED_EDGE('',*,*,#1015,.T.);
#1017=CARTESIAN_POINT('',(84.836,0.,8.12800000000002));
#1018=DIRECTION('',(0.,-1.,0.));
#1019=DIRECTION('',(1.,0.,0.));
#1020=AXIS2_PLACEMENT_3D('',#1017,#1018,#1019);
#1021=CIRCLE('',#1020,8.128);
#1022=CARTESIAN_POINT('',(84.836,0.,16.256));
#1023=VERTEX_POINT('',#1022);
#1024=EDGE_CURVE('E295',#1014,#1023,#1021,.T.);
#1025=ORIENTED_EDGE('',*,*,#1024,.T.);
#1026=DIRECTION('',(-1.,0.,0.));
#1027=VECTOR('',#1026,1.);
#1028=CARTESIAN_POINT('',(76.2,0.,16.256));
#1029=LINE('',#1028,#1027);
#1030=EDGE_CURVE('E282',#1023,#198,#1029,.T.);
#1031=ORIENTED_EDGE('',*,*,#1030,.T.);
#1032=ORIENTED_EDGE('',*,*,#199,.F.);
#1033=DIRECTION('',(-1.,0.,0.));
#1034=VECTOR('',#1033,1.);
#1035=CARTESIAN_POINT('',(76.2,0.,59.944));
#1036=LINE('',#1035,#1034);
#1037=CARTESIAN_POINT('',(84.836,0.,59.944));
#1038=VERTEX_POINT('',#1037);
#1039=EDGE_CURVE('E345',#1038,#196,#1036,.T.);
#1040=ORIENTED_EDGE('',*,*,#1039,.F.);
#1041=CARTESIAN_POINT('',(84.836,0.,68.072));
#1042=DIRECTION('',(0.,1.,0.));
#1043=DIRECTION('',(1.,0.,0.));
#1044=AXIS2_PLACEMENT_3D('',#1041,#1042,#1043);
#1045=CIRCLE('',#1044,8.128);
#1046=CARTESIAN_POINT('',(84.836,0.,76.2));
#1047=VERTEX_POINT('',#1046);
#1048=EDGE_CURVE('E355',#1047,#1038,#1045,.T.);
#1049=ORIENTED_EDGE('',*,*,#1048,.F.);
#1050=DIRECTION('',(1.,0.,0.));
#1051=VECTOR('',#1050,1.);
#1052=CARTESIAN_POINT('',(76.2,0.,76.2));
#1053=LINE('',#1052,#1051);
#1054=EDGE_CURVE('E751',#969,#1047,#1053,.T.);
#1055=ORIENTED_EDGE('',*,*,#1054,.F.);
#1056=ORIENTED_EDGE('',*,*,#970,.T.);
#1057=EDGE_LOOP('',(#1016,#1025,#1031,#1032,#1040,#1049,#1055,#1056));
#1058=FACE_BOUND('',#1057,.T.);
#1059=ADVANCED_FACE('F521',(#997,#1008,#1058),#986,.F.);
#1060=CARTESIAN_POINT('',(63.5,33.02,76.2));
#1061=DIRECTION('',(0.,-1.,0.));
#1062=DIRECTION('',(1.,0.,0.));
#1063=AXIS2_PLACEMENT_3D('',#1060,#1061,#1062);
#1064=PLANE('',#1063);
#1065=DIRECTION('',(-1.,0.,0.));
#1066=VECTOR('',#1065,1.);
#1067=CARTESIAN_POINT('',(63.5,33.02,0.));
#1068=LINE('',#1067,#1066);
#1069=CARTESIAN_POINT('',(63.5,33.02,0.));
#1070=VERTEX_POINT('',#1069);
#1071=EDGE_CURVE('E272',#222,#1070,#1068,.T.);
#1072=ORIENTED_EDGE('',*,*,#1071,.T.);
#1073=DIRECTION('',(0.,0.,-1.));
#1074=VECTOR('',#1073,1.);
#1075=CARTESIAN_POINT('',(63.5,33.02,76.2));
#1076=LINE('',#1075,#1074);
#1077=CARTESIAN_POINT('',(63.5,33.02,76.2));
#1078=VERTEX_POINT('',#1077);
#1079=EDGE_CURVE('E664',#1078,#1070,#1076,.T.);
#1080=ORIENTED_EDGE('',*,*,#1079,.F.);
#1081=DIRECTION('',(-1.,0.,0.));
#1082=VECTOR('',#1081,1.);
#1083=CARTESIAN_POINT('',(63.5,33.02,76.2));
#1084=LINE('',#1083,#1082);
#1085=EDGE_CURVE('E756',#230,#1078,#1084,.T.);
#1086=ORIENTED_EDGE('',*,*,#1085,.F.);
#1087=ORIENTED_EDGE('',*,*,#231,.T.);
#1088=EDGE_LOOP('',(#1072,#1080,#1086,#1087));
#1089=FACE_BOUND('',#1088,.T.);
#1090=ADVANCED_FACE('F517',(#1089),#1064,.F.);
#1091=CARTESIAN_POINT('',(63.5,39.37,76.2));
#1092=DIRECTION('',(-1.,0.,0.));
#1093=DIRECTION('',(0.,0.,1.));
#1094=AXIS2_PLACEMENT_3D('',#1091,#1092,#1093);
#1095=PLANE('',#1094);
#1096=DIRECTION('',(0.,1.,0.));
#1097=VECTOR('',#1096,1.);
#1098=CARTESIAN_POINT('',(63.5,39.37,0.));
#1099=LINE('',#1098,#1097);
#1100=EDGE_CURVE('E658',#1070,#281,#1099,.T.);
#1101=ORIENTED_EDGE('',*,*,#1100,.T.);
#1102=ORIENTED_EDGE('',*,*,#306,.F.);
#1103=DIRECTION('',(0.,1.,0.));
#1104=VECTOR('',#1103,1.);
#1105=CARTESIAN_POINT('',(63.5,39.37,76.2));
#1106=LINE('',#1105,#1104);
#1107=EDGE_CURVE('E665',#1078,#299,#1106,.T.);
#1108=ORIENTED_EDGE('',*,*,#1107,.F.);
#1109=ORIENTED_EDGE('',*,*,#1079,.T.);
#1110=EDGE_LOOP('',(#1101,#1102,#1108,#1109));
#1111=FACE_BOUND('',#1110,.T.);
#1112=ADVANCED_FACE('F511',(#1111),#1095,.F.);
#1113=CARTESIAN_POINT('',(63.5,39.37,76.2));
#1114=DIRECTION('',(0.,0.,-1.));
#1115=DIRECTION('',(-1.,0.,0.));
#1116=AXIS2_PLACEMENT_3D('',#1113,#1114,#1115);
#1117=PLANE('',#1116);
#1118=ORIENTED_EDGE('',*,*,#300,.T.);
#1119=ORIENTED_EDGE('',*,*,#336,.T.);
#1120=ORIENTED_EDGE('',*,*,#367,.T.);
#1121=ORIENTED_EDGE('',*,*,#398,.T.);
#1122=ORIENTED_EDGE('',*,*,#451,.T.);
#1123=ORIENTED_EDGE('',*,*,#482,.T.);
#1124=ORIENTED_EDGE('',*,*,#504,.T.);
#1125=ORIENTED_EDGE('',*,*,#114,.T.);
#1126=DIRECTION('',(-1.,0.,0.));
#1127=VECTOR('',#1126,1.);
#1128=CARTESIAN_POINT('',(-76.2,5.84200000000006,76.2));
#1129=LINE('',#1128,#1127);
#1130=CARTESIAN_POINT('',(-84.836,5.84200000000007,76.2));
#1131=VERTEX_POINT('',#1130);
#1132=EDGE_CURVE('E775',#105,#1131,#1129,.T.);
#1133=ORIENTED_EDGE('',*,*,#1132,.T.);
#1134=DIRECTION('',(0.,-1.,0.));
#1135=VECTOR('',#1134,1.);
#1136=CARTESIAN_POINT('',(-84.836,5.84200000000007,76.2));
#1137=LINE('',#1136,#1135);
#1138=EDGE_CURVE('E819',#1131,#560,#1137,.T.);
#1139=ORIENTED_EDGE('',*,*,#1138,.T.);
#1140=ORIENTED_EDGE('',*,*,#561,.T.);
#1141=ORIENTED_EDGE('',*,*,#622,.T.);
#1142=ORIENTED_EDGE('',*,*,#653,.T.);
#1143=ORIENTED_EDGE('',*,*,#684,.T.);
#1144=ORIENTED_EDGE('',*,*,#737,.T.);
#1145=ORIENTED_EDGE('',*,*,#768,.T.);
#1146=ORIENTED_EDGE('',*,*,#799,.T.);
#1147=ORIENTED_EDGE('',*,*,#830,.T.);
#1148=ORIENTED_EDGE('',*,*,#883,.T.);
#1149=ORIENTED_EDGE('',*,*,#914,.T.);
#1150=ORIENTED_EDGE('',*,*,#945,.T.);
#1151=ORIENTED_EDGE('',*,*,#976,.T.);
#1152=ORIENTED_EDGE('',*,*,#1054,.T.);
#1153=DIRECTION('',(0.,-1.,0.));
#1154=VECTOR('',#1153,1.);
#1155=CARTESIAN_POINT('',(84.836,5.84200000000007,76.2));
#1156=LINE('',#1155,#1154);
#1157=EDGE_CURVE('E357',#154,#1047,#1156,.T.);
#1158=ORIENTED_EDGE('',*,*,#1157,.F.);
#1159=ORIENTED_EDGE('',*,*,#155,.F.);
#1160=ORIENTED_EDGE('',*,*,#237,.T.);
#1161=ORIENTED_EDGE('',*,*,#1085,.T.);
#1162=ORIENTED_EDGE('',*,*,#1107,.T.);
#1163=EDGE_LOOP('',(#1118,#1119,#1120,#1121,#1122,#1123,#1124,#1125,#1133,#1139,#1140,#1141,
#1142,#1143,#1144,#1145,#1146,#1147,#1148,#1149,#1150,#1151,#1152,#1158,#1159,#1160,#1161,#1162));
#1164=FACE_BOUND('',#1163,.T.);
#1165=ADVANCED_FACE('F508',(#1164),#1117,.F.);
#1166=CARTESIAN_POINT('',(63.5,39.37,0.));
#1167=DIRECTION('',(0.,0.,-1.));
#1168=DIRECTION('',(-1.,0.,0.));
#1169=AXIS2_PLACEMENT_3D('',#1166,#1167,#1168);
#1170=PLANE('',#1169);
#1171=ORIENTED_EDGE('',*,*,#284,.F.);
#1172=ORIENTED_EDGE('',*,*,#1100,.F.);
#1173=ORIENTED_EDGE('',*,*,#1071,.F.);
#1174=ORIENTED_EDGE('',*,*,#223,.F.);
#1175=DIRECTION('',(1.,0.,0.));
#1176=VECTOR('',#1175,1.);
#1177=CARTESIAN_POINT('',(76.2,5.84200000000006,0.));
#1178=LINE('',#1177,#1176);
#1179=CARTESIAN_POINT('',(84.836,5.84200000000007,0.));
#1180=VERTEX_POINT('',#1179);
#1181=EDGE_CURVE('E270',#214,#1180,#1178,.T.);
#1182=ORIENTED_EDGE('',*,*,#1181,.T.);
#1183=DIRECTION('',(0.,-1.,0.));
#1184=VECTOR('',#1183,1.);
#1185=CARTESIAN_POINT('',(84.836,5.84200000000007,0.));
#1186=LINE('',#1185,#1184);
#1187=EDGE_CURVE('E294',#1180,#1014,#1186,.T.);
#1188=ORIENTED_EDGE('',*,*,#1187,.T.);
#1189=ORIENTED_EDGE('',*,*,#1015,.F.);
#1190=ORIENTED_EDGE('',*,*,#962,.F.);
#1191=ORIENTED_EDGE('',*,*,#931,.F.);
#1192=ORIENTED_EDGE('',*,*,#900,.F.);
#1193=ORIENTED_EDGE('',*,*,#869,.F.);
#1194=ORIENTED_EDGE('',*,*,#816,.F.);
#1195=ORIENTED_EDGE('',*,*,#785,.F.);
#1196=ORIENTED_EDGE('',*,*,#754,.F.);
#1197=ORIENTED_EDGE('',*,*,#723,.F.);
#1198=ORIENTED_EDGE('',*,*,#670,.F.);
#1199=ORIENTED_EDGE('',*,*,#639,.F.);
#1200=ORIENTED_EDGE('',*,*,#608,.F.);
#1201=ORIENTED_EDGE('',*,*,#545,.F.);
#1202=DIRECTION('',(0.,-1.,0.));
#1203=VECTOR('',#1202,1.);
#1204=CARTESIAN_POINT('',(-84.836,5.84200000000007,0.));
#1205=LINE('',#1204,#1203);
#1206=EDGE_CURVE('E331',#39,#542,#1205,.T.);
#1207=ORIENTED_EDGE('',*,*,#1206,.F.);
#1208=ORIENTED_EDGE('',*,*,#40,.F.);
#1209=ORIENTED_EDGE('',*,*,#128,.F.);
#1210=ORIENTED_EDGE('',*,*,#497,.F.);
#1211=ORIENTED_EDGE('',*,*,#468,.F.);
#1212=ORIENTED_EDGE('',*,*,#437,.F.);
#1213=ORIENTED_EDGE('',*,*,#384,.F.);
#1214=ORIENTED_EDGE('',*,*,#353,.F.);
#1215=ORIENTED_EDGE('',*,*,#322,.F.);
#1216=EDGE_LOOP('',(#1171,#1172,#1173,#1174,#1182,#1188,#1189,#1190,#1191,#1192,#1193,#1194,
#1195,#1196,#1197,#1198,#1199,#1200,#1201,#1207,#1208,#1209,#1210,#1211,#1212,#1213,#1214,#1215));
#1217=FACE_BOUND('',#1216,.T.);
#1218=ADVANCED_FACE('F267',(#1217),#1170,.T.);
#1219=CARTESIAN_POINT('',(-76.2,5.84200000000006,59.944));
#1220=DIRECTION('',(0.,0.,-1.));
#1221=DIRECTION('',(-1.,0.,0.));
#1222=AXIS2_PLACEMENT_3D('',#1219,#1220,#1221);
#1223=PLANE('',#1222);
#1224=ORIENTED_EDGE('',*,*,#576,.F.);
#1225=DIRECTION('',(0.,-1.,0.));
#1226=VECTOR('',#1225,1.);
#1227=CARTESIAN_POINT('',(-84.836,5.84200000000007,59.944));
#1228=LINE('',#1227,#1226);
#1229=CARTESIAN_POINT('',(-84.836,5.84200000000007,59.944));
#1230=VERTEX_POINT('',#1229);
#1231=EDGE_CURVE('E773',#1230,#569,#1228,.T.);
#1232=ORIENTED_EDGE('',*,*,#1231,.F.);
#1233=DIRECTION('',(1.,0.,0.));
#1234=VECTOR('',#1233,1.);
#1235=CARTESIAN_POINT('',(-76.2,5.84200000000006,59.944));
#1236=LINE('',#1235,#1234);
#1237=EDGE_CURVE('E780',#1230,#97,#1236,.T.);
#1238=ORIENTED_EDGE('',*,*,#1237,.T.);
#1239=ORIENTED_EDGE('',*,*,#98,.T.);
#1240=EDGE_LOOP('',(#1224,#1232,#1238,#1239));
#1241=FACE_BOUND('',#1240,.T.);
#1242=ADVANCED_FACE('F501',(#1241),#1223,.T.);
#1243=CARTESIAN_POINT('',(-84.836,5.84200000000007,68.072));
#1244=DIRECTION('',(0.,-1.,0.));
#1245=DIRECTION('',(1.,0.,0.));
#1246=AXIS2_PLACEMENT_3D('',#1243,#1244,#1245);
#1247=CYLINDRICAL_SURFACE('',#1246,8.128);
#1248=ORIENTED_EDGE('',*,*,#570,.F.);
#1249=ORIENTED_EDGE('',*,*,#1138,.F.);
#1250=CARTESIAN_POINT('',(-84.836,5.84200000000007,68.072));
#1251=DIRECTION('',(0.,-1.,0.));
#1252=DIRECTION('',(-1.,0.,0.));
#1253=AXIS2_PLACEMENT_3D('',#1250,#1251,#1252);
#1254=CIRCLE('',#1253,8.128);
#1255=EDGE_CURVE('E777',#1131,#1230,#1254,.T.);
#1256=ORIENTED_EDGE('',*,*,#1255,.T.);
#1257=ORIENTED_EDGE('',*,*,#1231,.T.);
#1258=EDGE_LOOP('',(#1248,#1249,#1256,#1257));
#1259=FACE_BOUND('',#1258,.T.);
#1260=ADVANCED_FACE('F499',(#1259),#1247,.T.);
#1261=CARTESIAN_POINT('',(-84.836,5.84200000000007,68.072));
#1262=DIRECTION('',(0.,1.,0.));
#1263=DIRECTION('',(-1.,0.,0.));
#1264=AXIS2_PLACEMENT_3D('',#1261,#1262,#1263);
#1265=PLANE('',#1264);
#1266=CARTESIAN_POINT('',(-84.836,5.84200000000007,68.072));
#1267=DIRECTION('',(0.,1.,0.));
#1268=DIRECTION('',(-1.,0.,0.));
#1269=AXIS2_PLACEMENT_3D('',#1266,#1267,#1268);
#1270=CIRCLE('',#1269,4.95300000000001);
#1271=CARTESIAN_POINT('',(-89.789,5.84200000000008,68.072));
#1272=VERTEX_POINT('',#1271);
#1273=EDGE_CURVE('E762',#1272,#1272,#1270,.T.);
#1274=ORIENTED_EDGE('',*,*,#1273,.F.);
#1275=EDGE_LOOP('',(#1274));
#1276=FACE_BOUND('',#1275,.T.);
#1277=ORIENTED_EDGE('',*,*,#106,.F.);
#1278=ORIENTED_EDGE('',*,*,#1237,.F.);
#1279=ORIENTED_EDGE('',*,*,#1255,.F.);
#1280=ORIENTED_EDGE('',*,*,#1132,.F.);
#1281=EDGE_LOOP('',(#1277,#1278,#1279,#1280));
#1282=FACE_BOUND('',#1281,.T.);
#1283=ADVANCED_FACE('F495',(#1276,#1282),#1265,.T.);
#1284=CARTESIAN_POINT('',(-84.836,4.57200000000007,68.072));
#1285=DIRECTION('',(0.,1.,0.));
#1286=DIRECTION('',(-1.,0.,0.));
#1287=AXIS2_PLACEMENT_3D('',#1284,#1285,#1286);
#1288=CYLINDRICAL_SURFACE('',#1287,4.95300000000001);
#1289=CARTESIAN_POINT('',(-84.836,4.57200000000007,68.072));
#1290=DIRECTION('',(0.,1.,0.));
#1291=DIRECTION('',(-1.,0.,0.));
#1292=AXIS2_PLACEMENT_3D('',#1289,#1290,#1291);
#1293=CIRCLE('',#1292,4.95300000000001);
#1294=CARTESIAN_POINT('',(-89.789,4.57200000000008,68.072));
#1295=VERTEX_POINT('',#1294);
#1296=EDGE_CURVE('E824',#1295,#1295,#1293,.T.);
#1297=ORIENTED_EDGE('',*,*,#1296,.F.);
#1298=EDGE_LOOP('',(#1297));
#1299=FACE_BOUND('',#1298,.T.);
#1300=ORIENTED_EDGE('',*,*,#1273,.T.);
#1301=EDGE_LOOP('',(#1300));
#1302=FACE_BOUND('',#1301,.T.);
#1303=ADVANCED_FACE('F491',(#1299,#1302),#1288,.F.);
#1304=CARTESIAN_POINT('',(-84.836,4.57200000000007,68.072));
#1305=DIRECTION('',(0.,1.,0.));
#1306=DIRECTION('',(-1.,0.,0.));
#1307=AXIS2_PLACEMENT_3D('',#1304,#1305,#1306);
#1308=PLANE('',#1307);
#1309=CARTESIAN_POINT('',(-84.836,4.57200000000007,68.072));
#1310=DIRECTION('',(0.,1.,0.));
#1311=DIRECTION('',(0.,0.,1.));
#1312=AXIS2_PLACEMENT_3D('',#1309,#1310,#1311);
#1313=CIRCLE('',#1312,3.02259999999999);
#1314=CARTESIAN_POINT('',(-84.836,4.57200000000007,71.0946));
#1315=VERTEX_POINT('',#1314);
#1316=EDGE_CURVE('E360',#1315,#1315,#1313,.T.);
#1317=ORIENTED_EDGE('',*,*,#1316,.F.);
#1318=EDGE_LOOP('',(#1317));
#1319=FACE_BOUND('',#1318,.T.);
#1320=ORIENTED_EDGE('',*,*,#1296,.T.);
#1321=EDGE_LOOP('',(#1320));
#1322=FACE_BOUND('',#1321,.T.);
#1323=ADVANCED_FACE('F487',(#1319,#1322),#1308,.T.);
#1324=CARTESIAN_POINT('',(-84.836,4.57200000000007,68.072));
#1325=DIRECTION('',(0.,1.,0.));
#1326=DIRECTION('',(0.,0.,1.));
#1327=AXIS2_PLACEMENT_3D('',#1324,#1325,#1326);
#1328=CYLINDRICAL_SURFACE('',#1327,3.02259999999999);
#1329=ORIENTED_EDGE('',*,*,#1316,.T.);
#1330=EDGE_LOOP('',(#1329));
#1331=FACE_BOUND('',#1330,.T.);
#1332=ORIENTED_EDGE('',*,*,#533,.F.);
#1333=EDGE_LOOP('',(#1332));
#1334=FACE_BOUND('',#1333,.T.);
#1335=ADVANCED_FACE('F480',(#1331,#1334),#1328,.F.);
#1336=CARTESIAN_POINT('',(84.836,5.84200000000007,68.072));
#1337=DIRECTION('',(0.,-1.,0.));
#1338=DIRECTION('',(1.,0.,0.));
#1339=AXIS2_PLACEMENT_3D('',#1336,#1337,#1338);
#1340=CYLINDRICAL_SURFACE('',#1339,8.128);
#1341=ORIENTED_EDGE('',*,*,#1048,.T.);
#1342=DIRECTION('',(0.,-1.,0.));
#1343=VECTOR('',#1342,1.);
#1344=CARTESIAN_POINT('',(84.836,5.84200000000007,59.944));
#1345=LINE('',#1344,#1343);
#1346=EDGE_CURVE('E361',#163,#1038,#1345,.T.);
#1347=ORIENTED_EDGE('',*,*,#1346,.F.);
#1348=ORIENTED_EDGE('',*,*,#164,.F.);
#1349=ORIENTED_EDGE('',*,*,#1157,.T.);
#1350=EDGE_LOOP('',(#1341,#1347,#1348,#1349));
#1351=FACE_BOUND('',#1350,.T.);
#1352=ADVANCED_FACE('F477',(#1351),#1340,.T.);
#1353=CARTESIAN_POINT('',(76.2,5.84200000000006,59.944));
#1354=DIRECTION('',(0.,0.,1.));
#1355=DIRECTION('',(1.,0.,0.));
#1356=AXIS2_PLACEMENT_3D('',#1353,#1354,#1355);
#1357=PLANE('',#1356);
#1358=ORIENTED_EDGE('',*,*,#1039,.T.);
#1359=ORIENTED_EDGE('',*,*,#244,.F.);
#1360=ORIENTED_EDGE('',*,*,#170,.F.);
#1361=ORIENTED_EDGE('',*,*,#1346,.T.);
#1362=EDGE_LOOP('',(#1358,#1359,#1360,#1361));
#1363=FACE_BOUND('',#1362,.T.);
#1364=ADVANCED_FACE('F472',(#1363),#1357,.F.);
#1365=CARTESIAN_POINT('',(84.836,4.57200000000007,68.072));
#1366=DIRECTION('',(0.,1.,0.));
#1367=DIRECTION('',(-1.,0.,0.));
#1368=AXIS2_PLACEMENT_3D('',#1365,#1366,#1367);
#1369=CYLINDRICAL_SURFACE('',#1368,4.95300000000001);
#1370=CARTESIAN_POINT('',(84.836,4.57200000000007,68.072));
#1371=DIRECTION('',(0.,-1.,0.));
#1372=DIRECTION('',(1.,0.,0.));
#1373=AXIS2_PLACEMENT_3D('',#1370,#1371,#1372);
#1374=CIRCLE('',#1373,4.95300000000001);
#1375=CARTESIAN_POINT('',(89.789,4.57200000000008,68.072));
#1376=VERTEX_POINT('',#1375);
#1377=EDGE_CURVE('E342',#1376,#1376,#1374,.T.);
#1378=ORIENTED_EDGE('',*,*,#1377,.T.);
#1379=EDGE_LOOP('',(#1378));
#1380=FACE_BOUND('',#1379,.T.);
#1381=ORIENTED_EDGE('',*,*,#181,.F.);
#1382=EDGE_LOOP('',(#1381));
#1383=FACE_BOUND('',#1382,.T.);
#1384=ADVANCED_FACE('F468',(#1380,#1383),#1369,.F.);
#1385=CARTESIAN_POINT('',(84.836,4.57200000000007,68.072));
#1386=DIRECTION('',(0.,1.,0.));
#1387=DIRECTION('',(1.,0.,0.));
#1388=AXIS2_PLACEMENT_3D('',#1385,#1386,#1387);
#1389=PLANE('',#1388);
#1390=CARTESIAN_POINT('',(84.836,4.57200000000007,68.072));
#1391=DIRECTION('',(0.,1.,0.));
#1392=DIRECTION('',(0.,0.,1.));
#1393=AXIS2_PLACEMENT_3D('',#1390,#1391,#1392);
#1394=CIRCLE('',#1393,3.02259999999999);
#1395=CARTESIAN_POINT('',(84.836,4.57200000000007,71.0946));
#1396=VERTEX_POINT('',#1395);
#1397=EDGE_CURVE('E334',#1396,#1396,#1394,.T.);
#1398=ORIENTED_EDGE('',*,*,#1397,.F.);
#1399=EDGE_LOOP('',(#1398));
#1400=FACE_BOUND('',#1399,.T.);
#1401=ORIENTED_EDGE('',*,*,#1377,.F.);
#1402=EDGE_LOOP('',(#1401));
#1403=FACE_BOUND('',#1402,.T.);
#1404=ADVANCED_FACE('F464',(#1400,#1403),#1389,.T.);
#1405=CARTESIAN_POINT('',(84.836,4.57200000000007,68.072));
#1406=DIRECTION('',(0.,1.,0.));
#1407=DIRECTION('',(0.,0.,1.));
#1408=AXIS2_PLACEMENT_3D('',#1405,#1406,#1407);
#1409=CYLINDRICAL_SURFACE('',#1408,3.02259999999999);
#1410=ORIENTED_EDGE('',*,*,#1397,.T.);
#1411=EDGE_LOOP('',(#1410));
#1412=FACE_BOUND('',#1411,.T.);
#1413=ORIENTED_EDGE('',*,*,#1005,.F.);
#1414=EDGE_LOOP('',(#1413));
#1415=FACE_BOUND('',#1414,.T.);
#1416=ADVANCED_FACE('F457',(#1412,#1415),#1409,.F.);
#1417=CARTESIAN_POINT('',(-84.836,5.84200000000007,8.12800000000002));
#1418=DIRECTION('',(0.,-1.,0.));
#1419=DIRECTION('',(1.,0.,0.));
#1420=AXIS2_PLACEMENT_3D('',#1417,#1418,#1419);
#1421=CYLINDRICAL_SURFACE('',#1420,8.128);
#1422=ORIENTED_EDGE('',*,*,#592,.T.);
#1423=DIRECTION('',(0.,-1.,0.));
#1424=VECTOR('',#1423,1.);
#1425=CARTESIAN_POINT('',(-84.836,5.84200000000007,16.256));
#1426=LINE('',#1425,#1424);
#1427=EDGE_CURVE('E335',#48,#584,#1426,.T.);
#1428=ORIENTED_EDGE('',*,*,#1427,.F.);
#1429=ORIENTED_EDGE('',*,*,#49,.F.);
#1430=ORIENTED_EDGE('',*,*,#1206,.T.);
#1431=EDGE_LOOP('',(#1422,#1428,#1429,#1430));
#1432=FACE_BOUND('',#1431,.T.);
#1433=ADVANCED_FACE('F453',(#1432),#1421,.T.);
#1434=CARTESIAN_POINT('',(-76.2,5.84200000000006,16.256));
#1435=DIRECTION('',(0.,0.,-1.));
#1436=DIRECTION('',(-1.,0.,0.));
#1437=AXIS2_PLACEMENT_3D('',#1434,#1435,#1436);
#1438=PLANE('',#1437);
#1439=ORIENTED_EDGE('',*,*,#585,.T.);
#1440=ORIENTED_EDGE('',*,*,#82,.F.);
#1441=ORIENTED_EDGE('',*,*,#55,.F.);
#1442=ORIENTED_EDGE('',*,*,#1427,.T.);
#1443=EDGE_LOOP('',(#1439,#1440,#1441,#1442));
#1444=FACE_BOUND('',#1443,.T.);
#1445=ADVANCED_FACE('F456',(#1444),#1438,.F.);
#1446=CARTESIAN_POINT('',(-84.836,4.57200000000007,8.12800000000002));
#1447=DIRECTION('',(0.,1.,0.));
#1448=DIRECTION('',(-1.,0.,0.));
#1449=AXIS2_PLACEMENT_3D('',#1446,#1447,#1448);
#1450=CYLINDRICAL_SURFACE('',#1449,4.95300000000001);
#1451=CARTESIAN_POINT('',(-84.836,4.57200000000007,8.12800000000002));
#1452=DIRECTION('',(0.,-1.,0.));
#1453=DIRECTION('',(-1.,0.,0.));
#1454=AXIS2_PLACEMENT_3D('',#1451,#1452,#1453);
#1455=CIRCLE('',#1454,4.95300000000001);
#1456=CARTESIAN_POINT('',(-89.789,4.57200000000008,8.12800000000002));
#1457=VERTEX_POINT('',#1456);
#1458=EDGE_CURVE('E309',#1457,#1457,#1455,.T.);
#1459=ORIENTED_EDGE('',*,*,#1458,.T.);
#1460=EDGE_LOOP('',(#1459));
#1461=FACE_BOUND('',#1460,.T.);
#1462=ORIENTED_EDGE('',*,*,#66,.F.);
#1463=EDGE_LOOP('',(#1462));
#1464=FACE_BOUND('',#1463,.T.);
#1465=ADVANCED_FACE('F451',(#1461,#1464),#1450,.F.);
#1466=CARTESIAN_POINT('',(-84.836,4.57200000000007,8.12800000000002));
#1467=DIRECTION('',(0.,1.,0.));
#1468=DIRECTION('',(-1.,0.,0.));
#1469=AXIS2_PLACEMENT_3D('',#1466,#1467,#1468);
#1470=PLANE('',#1469);
#1471=CARTESIAN_POINT('',(-84.836,4.57200000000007,8.12800000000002));
#1472=DIRECTION('',(0.,1.,0.));
#1473=DIRECTION('',(0.,0.,1.));
#1474=AXIS2_PLACEMENT_3D('',#1471,#1472,#1473);
#1475=CIRCLE('',#1474,3.02259999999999);
#1476=CARTESIAN_POINT('',(-84.836,4.57200000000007,11.1506));
#1477=VERTEX_POINT('',#1476);
#1478=EDGE_CURVE('E302',#1477,#1477,#1475,.T.);
#1479=ORIENTED_EDGE('',*,*,#1478,.F.);
#1480=EDGE_LOOP('',(#1479));
#1481=FACE_BOUND('',#1480,.T.);
#1482=ORIENTED_EDGE('',*,*,#1458,.F.);
#1483=EDGE_LOOP('',(#1482));
#1484=FACE_BOUND('',#1483,.T.);
#1485=ADVANCED_FACE('F913',(#1481,#1484),#1470,.T.);
#1486=CARTESIAN_POINT('',(-84.836,4.57200000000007,8.12800000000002));
#1487=DIRECTION('',(0.,1.,0.));
#1488=DIRECTION('',(0.,0.,1.));
#1489=AXIS2_PLACEMENT_3D('',#1486,#1487,#1488);
#1490=CYLINDRICAL_SURFACE('',#1489,3.02259999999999);
#1491=ORIENTED_EDGE('',*,*,#1478,.T.);
#1492=EDGE_LOOP('',(#1491));
#1493=FACE_BOUND('',#1492,.T.);
#1494=ORIENTED_EDGE('',*,*,#522,.F.);
#1495=EDGE_LOOP('',(#1494));
#1496=FACE_BOUND('',#1495,.T.);
#1497=ADVANCED_FACE('F909',(#1493,#1496),#1490,.F.);
#1498=CARTESIAN_POINT('',(76.2,5.84200000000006,16.256));
#1499=DIRECTION('',(0.,0.,1.));
#1500=DIRECTION('',(1.,0.,0.));
#1501=AXIS2_PLACEMENT_3D('',#1498,#1499,#1500);
#1502=PLANE('',#1501);
#1503=ORIENTED_EDGE('',*,*,#1030,.F.);
#1504=DIRECTION('',(0.,-1.,0.));
#1505=VECTOR('',#1504,1.);
#1506=CARTESIAN_POINT('',(84.836,5.84200000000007,16.256));
#1507=LINE('',#1506,#1505);
#1508=CARTESIAN_POINT('',(84.836,5.84200000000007,16.256));
#1509=VERTEX_POINT('',#1508);
#1510=EDGE_CURVE('E303',#1509,#1023,#1507,.T.);
#1511=ORIENTED_EDGE('',*,*,#1510,.F.);
#1512=DIRECTION('',(-1.,0.,0.));
#1513=VECTOR('',#1512,1.);
#1514=CARTESIAN_POINT('',(76.2,5.84200000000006,16.256));
#1515=LINE('',#1514,#1513);
#1516=EDGE_CURVE('E289',#1509,#206,#1515,.T.);
#1517=ORIENTED_EDGE('',*,*,#1516,.T.);
#1518=ORIENTED_EDGE('',*,*,#207,.T.);
#1519=EDGE_LOOP('',(#1503,#1511,#1517,#1518));
#1520=FACE_BOUND('',#1519,.T.);
#1521=ADVANCED_FACE('F434',(#1520),#1502,.T.);
#1522=CARTESIAN_POINT('',(84.836,5.84200000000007,8.12800000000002));
#1523=DIRECTION('',(0.,-1.,0.));
#1524=DIRECTION('',(1.,0.,0.));
#1525=AXIS2_PLACEMENT_3D('',#1522,#1523,#1524);
#1526=CYLINDRICAL_SURFACE('',#1525,8.128);
#1527=ORIENTED_EDGE('',*,*,#1024,.F.);
#1528=ORIENTED_EDGE('',*,*,#1187,.F.);
#1529=CARTESIAN_POINT('',(84.836,5.84200000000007,8.12800000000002));
#1530=DIRECTION('',(0.,-1.,0.));
#1531=DIRECTION('',(1.,0.,0.));
#1532=AXIS2_PLACEMENT_3D('',#1529,#1530,#1531);
#1533=CIRCLE('',#1532,8.128);
#1534=EDGE_CURVE('E287',#1180,#1509,#1533,.T.);
#1535=ORIENTED_EDGE('',*,*,#1534,.T.);
#1536=ORIENTED_EDGE('',*,*,#1510,.T.);
#1537=EDGE_LOOP('',(#1527,#1528,#1535,#1536));
#1538=FACE_BOUND('',#1537,.T.);
#1539=ADVANCED_FACE('F425',(#1538),#1526,.T.);
#1540=CARTESIAN_POINT('',(84.836,5.84200000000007,8.12800000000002));
#1541=DIRECTION('',(0.,1.,0.));
#1542=DIRECTION('',(1.,0.,0.));
#1543=AXIS2_PLACEMENT_3D('',#1540,#1541,#1542);
#1544=PLANE('',#1543);
#1545=CARTESIAN_POINT('',(84.836,5.84200000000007,8.12800000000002));
#1546=DIRECTION('',(0.,1.,0.));
#1547=DIRECTION('',(1.,0.,0.));
#1548=AXIS2_PLACEMENT_3D('',#1545,#1546,#1547);
#1549=CIRCLE('',#1548,4.95300000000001);
#1550=CARTESIAN_POINT('',(89.789,5.84200000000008,8.12800000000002));
#1551=VERTEX_POINT('',#1550);
#1552=EDGE_CURVE('E390',#1551,#1551,#1549,.T.);
#1553=ORIENTED_EDGE('',*,*,#1552,.F.);
#1554=EDGE_LOOP('',(#1553));
#1555=FACE_BOUND('',#1554,.T.);
#1556=ORIENTED_EDGE('',*,*,#215,.F.);
#1557=ORIENTED_EDGE('',*,*,#1516,.F.);
#1558=ORIENTED_EDGE('',*,*,#1534,.F.);
#1559=ORIENTED_EDGE('',*,*,#1181,.F.);
#1560=EDGE_LOOP('',(#1556,#1557,#1558,#1559));
#1561=FACE_BOUND('',#1560,.T.);
#1562=ADVANCED_FACE('F285',(#1555,#1561),#1544,.T.);
#1563=CARTESIAN_POINT('',(84.836,4.57200000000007,8.12800000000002));
#1564=DIRECTION('',(0.,1.,0.));
#1565=DIRECTION('',(-1.,0.,0.));
#1566=AXIS2_PLACEMENT_3D('',#1563,#1564,#1565);
#1567=CYLINDRICAL_SURFACE('',#1566,4.95300000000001);
#1568=CARTESIAN_POINT('',(84.836,4.57200000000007,8.12800000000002));
#1569=DIRECTION('',(0.,1.,0.));
#1570=DIRECTION('',(1.,0.,0.));
#1571=AXIS2_PLACEMENT_3D('',#1568,#1569,#1570);
#1572=CIRCLE('',#1571,4.95300000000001);
#1573=CARTESIAN_POINT('',(89.789,4.57200000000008,8.12800000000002));
#1574=VERTEX_POINT('',#1573);
#1575=EDGE_CURVE('E298',#1574,#1574,#1572,.T.);
#1576=ORIENTED_EDGE('',*,*,#1575,.F.);
#1577=EDGE_LOOP('',(#1576));
#1578=FACE_BOUND('',#1577,.T.);
#1579=ORIENTED_EDGE('',*,*,#1552,.T.);
#1580=EDGE_LOOP('',(#1579));
#1581=FACE_BOUND('',#1580,.T.);
#1582=ADVANCED_FACE('F422',(#1578,#1581),#1567,.F.);
#1583=CARTESIAN_POINT('',(84.836,4.57200000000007,8.12800000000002));
#1584=DIRECTION('',(0.,1.,0.));
#1585=DIRECTION('',(1.,0.,0.));
#1586=AXIS2_PLACEMENT_3D('',#1583,#1584,#1585);
#1587=PLANE('',#1586);
#1588=CARTESIAN_POINT('',(84.836,4.57200000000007,8.12800000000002));
#1589=DIRECTION('',(0.,1.,0.));
#1590=DIRECTION('',(0.,0.,1.));
#1591=AXIS2_PLACEMENT_3D('',#1588,#1589,#1590);
#1592=CIRCLE('',#1591,3.02259999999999);
#1593=CARTESIAN_POINT('',(84.836,4.57200000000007,11.1506));
#1594=VERTEX_POINT('',#1593);
#1595=EDGE_CURVE('E391',#1594,#1594,#1592,.T.);
#1596=ORIENTED_EDGE('',*,*,#1595,.F.);
#1597=EDGE_LOOP('',(#1596));
#1598=FACE_BOUND('',#1597,.T.);
#1599=ORIENTED_EDGE('',*,*,#1575,.T.);
#1600=EDGE_LOOP('',(#1599));
#1601=FACE_BOUND('',#1600,.T.);
#1602=ADVANCED_FACE('F431',(#1598,#1601),#1587,.T.);
#1603=CARTESIAN_POINT('',(84.836,4.57200000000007,8.12800000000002));
#1604=DIRECTION('',(0.,1.,0.));
#1605=DIRECTION('',(0.,0.,1.));
#1606=AXIS2_PLACEMENT_3D('',#1603,#1604,#1605);
#1607=CYLINDRICAL_SURFACE('',#1606,3.02259999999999);
#1608=ORIENTED_EDGE('',*,*,#1595,.T.);
#1609=EDGE_LOOP('',(#1608));
#1610=FACE_BOUND('',#1609,.T.);
#1611=ORIENTED_EDGE('',*,*,#994,.F.);
#1612=EDGE_LOOP('',(#1611));
#1613=FACE_BOUND('',#1612,.T.);
#1614=ADVANCED_FACE('F1092',(#1610,#1613),#1607,.F.);
#1615=CARTESIAN_POINT('',(-41.783,-5.00000000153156E-05,8.12800000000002));
#1616=DIRECTION('',(0.,1.,0.));
#1617=DIRECTION('',(-1.,0.,0.));
#1618=AXIS2_PLACEMENT_3D('',#1615,#1616,#1617);
#1619=CYLINDRICAL_SURFACE('',#1618,3.02259999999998);
#1620=ORIENTED_EDGE('',*,*,#427,.T.);
#1621=EDGE_LOOP('',(#1620));
#1622=FACE_BOUND('',#1621,.T.);
#1623=ORIENTED_EDGE('',*,*,#713,.F.);
#1624=EDGE_LOOP('',(#1623));
#1625=FACE_BOUND('',#1624,.T.);
#1626=ADVANCED_FACE('F1097',(#1622,#1625),#1619,.F.);
#1627=CARTESIAN_POINT('',(-41.783,-5.00000000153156E-05,68.072));
#1628=DIRECTION('',(0.,1.,0.));
#1629=DIRECTION('',(-1.,0.,0.));
#1630=AXIS2_PLACEMENT_3D('',#1627,#1628,#1629);
#1631=CYLINDRICAL_SURFACE('',#1630,3.02259999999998);
#1632=ORIENTED_EDGE('',*,*,#416,.T.);
#1633=EDGE_LOOP('',(#1632));
#1634=FACE_BOUND('',#1633,.T.);
#1635=ORIENTED_EDGE('',*,*,#702,.F.);
#1636=EDGE_LOOP('',(#1635));
#1637=FACE_BOUND('',#1636,.T.);
#1638=ADVANCED_FACE('F1261',(#1634,#1637),#1631,.F.);
#1639=CARTESIAN_POINT('',(41.783,-5.00000000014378E-05,8.12800000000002));
#1640=DIRECTION('',(0.,1.,0.));
#1641=DIRECTION('',(-1.,0.,0.));
#1642=AXIS2_PLACEMENT_3D('',#1639,#1640,#1641);
#1643=CYLINDRICAL_SURFACE('',#1642,3.02259999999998);
#1644=ORIENTED_EDGE('',*,*,#272,.T.);
#1645=EDGE_LOOP('',(#1644));
#1646=FACE_BOUND('',#1645,.T.);
#1647=ORIENTED_EDGE('',*,*,#859,.F.);
#1648=EDGE_LOOP('',(#1647));
#1649=FACE_BOUND('',#1648,.T.);
#1650=ADVANCED_FACE('F1265',(#1646,#1649),#1643,.F.);
#1651=CARTESIAN_POINT('',(41.783,-5.00000000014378E-05,68.072));
#1652=DIRECTION('',(0.,1.,0.));
#1653=DIRECTION('',(-1.,0.,0.));
#1654=AXIS2_PLACEMENT_3D('',#1651,#1652,#1653);
#1655=CYLINDRICAL_SURFACE('',#1654,3.02259999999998);
#1656=ORIENTED_EDGE('',*,*,#261,.T.);
#1657=EDGE_LOOP('',(#1656));
#1658=FACE_BOUND('',#1657,.T.);
#1659=ORIENTED_EDGE('',*,*,#848,.F.);
#1660=EDGE_LOOP('',(#1659));
#1661=FACE_BOUND('',#1660,.T.);
#1662=ADVANCED_FACE('F1269',(#1658,#1661),#1655,.F.);
#1663=CLOSED_SHELL('',(#70,#133,#185,#248,#310,#341,#372,#403,#456,#487,#509,#596,#627,#658,
#689,#742,#773,#804,#835,#888,#919,#950,#981,#1059,#1090,#1112,#1165,#1218,#1242,#1260,#1283,
#1303,#1323,#1335,#1352,#1364,#1384,#1404,#1416,#1433,#1445,#1465,#1485,#1497,#1521,#1539,#1562,
#1582,#1602,#1614,#1626,#1638,#1650,#1662));
#1664=MANIFOLD_SOLID_BREP('B2',#1663);
#1665=ADVANCED_BREP_SHAPE_REPRESENTATION('',(#18,#1664),#14);
#1666=SHAPE_DEFINITION_REPRESENTATION(#9,#1665);
ENDSEC;
END-ISO-10303-21;
